VERSION 5.8 ;
BUSBITCHARS "[]" ;
DIVIDERCHAR "/" ;
UNITS
    DATABASE MICRONS 1000 ;
END UNITS

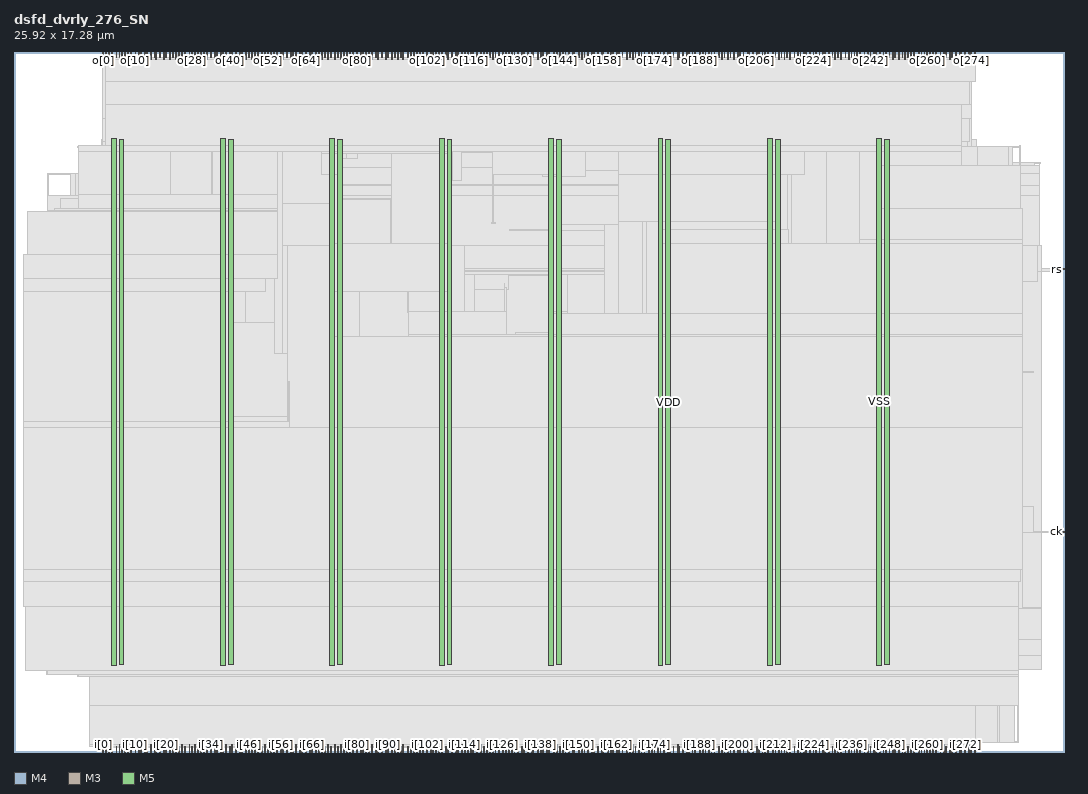
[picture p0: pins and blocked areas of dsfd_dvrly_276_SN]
MACRO dsfd_dvrly_276_SN
  FOREIGN dsfd_dvrly_276_SN 0 0 ;
  CLASS BLOCK ;
  SIZE 25.92 BY 17.28 ;
  PIN ck
    DIRECTION INPUT ;
    USE SIGNAL ;
    PORT
      LAYER M4 ;
        RECT  25.728 5.424 25.92 5.448 ;
    END
  END ck
  PIN i[0]
    DIRECTION INPUT ;
    USE SIGNAL ;
    PORT
      LAYER M3 ;
        RECT  2.196 0 2.214 0.144 ;
    END
  END i[0]
  PIN i[100]
    DIRECTION INPUT ;
    USE SIGNAL ;
    PORT
      LAYER M3 ;
        RECT  10.008 0 10.026 0.144 ;
    END
  END i[100]
  PIN i[101]
    DIRECTION INPUT ;
    USE SIGNAL ;
    PORT
      LAYER M5 ;
        RECT  10.08 0 10.104 0.192 ;
    END
  END i[101]
  PIN i[102]
    DIRECTION INPUT ;
    USE SIGNAL ;
    PORT
      LAYER M3 ;
        RECT  10.188 0 10.206 0.144 ;
    END
  END i[102]
  PIN i[103]
    DIRECTION INPUT ;
    USE SIGNAL ;
    PORT
      LAYER M5 ;
        RECT  10.272 0 10.296 0.192 ;
    END
  END i[103]
  PIN i[104]
    DIRECTION INPUT ;
    USE SIGNAL ;
    PORT
      LAYER M3 ;
        RECT  10.332 0 10.35 0.144 ;
    END
  END i[104]
  PIN i[105]
    DIRECTION INPUT ;
    USE SIGNAL ;
    PORT
      LAYER M5 ;
        RECT  10.416 0 10.44 0.192 ;
    END
  END i[105]
  PIN i[106]
    DIRECTION INPUT ;
    USE SIGNAL ;
    PORT
      LAYER M3 ;
        RECT  10.476 0 10.494 0.144 ;
    END
  END i[106]
  PIN i[107]
    DIRECTION INPUT ;
    USE SIGNAL ;
    PORT
      LAYER M5 ;
        RECT  10.56 0 10.584 0.192 ;
    END
  END i[107]
  PIN i[108]
    DIRECTION INPUT ;
    USE SIGNAL ;
    PORT
      LAYER M3 ;
        RECT  10.656 0 10.674 0.144 ;
    END
  END i[108]
  PIN i[109]
    DIRECTION INPUT ;
    USE SIGNAL ;
    PORT
      LAYER M5 ;
        RECT  10.704 0 10.728 0.192 ;
    END
  END i[109]
  PIN i[10]
    DIRECTION INPUT ;
    USE SIGNAL ;
    PORT
      LAYER M3 ;
        RECT  2.988 0 3.006 0.144 ;
    END
  END i[10]
  PIN i[110]
    DIRECTION INPUT ;
    USE SIGNAL ;
    PORT
      LAYER M3 ;
        RECT  10.8 0 10.818 0.144 ;
    END
  END i[110]
  PIN i[111]
    DIRECTION INPUT ;
    USE SIGNAL ;
    PORT
      LAYER M5 ;
        RECT  10.896 0 10.92 0.192 ;
    END
  END i[111]
  PIN i[112]
    DIRECTION INPUT ;
    USE SIGNAL ;
    PORT
      LAYER M3 ;
        RECT  10.944 0 10.962 0.144 ;
    END
  END i[112]
  PIN i[113]
    DIRECTION INPUT ;
    USE SIGNAL ;
    PORT
      LAYER M5 ;
        RECT  11.04 0 11.064 0.192 ;
    END
  END i[113]
  PIN i[114]
    DIRECTION INPUT ;
    USE SIGNAL ;
    PORT
      LAYER M3 ;
        RECT  11.124 0 11.142 0.144 ;
    END
  END i[114]
  PIN i[115]
    DIRECTION INPUT ;
    USE SIGNAL ;
    PORT
      LAYER M5 ;
        RECT  11.184 0 11.208 0.192 ;
    END
  END i[115]
  PIN i[116]
    DIRECTION INPUT ;
    USE SIGNAL ;
    PORT
      LAYER M3 ;
        RECT  11.268 0 11.286 0.144 ;
    END
  END i[116]
  PIN i[117]
    DIRECTION INPUT ;
    USE SIGNAL ;
    PORT
      LAYER M5 ;
        RECT  11.328 0 11.352 0.192 ;
    END
  END i[117]
  PIN i[118]
    DIRECTION INPUT ;
    USE SIGNAL ;
    PORT
      LAYER M3 ;
        RECT  11.412 0 11.43 0.144 ;
    END
  END i[118]
  PIN i[119]
    DIRECTION INPUT ;
    USE SIGNAL ;
    PORT
      LAYER M5 ;
        RECT  11.52 0 11.544 0.192 ;
    END
  END i[119]
  PIN i[11]
    DIRECTION INPUT ;
    USE SIGNAL ;
    PORT
      LAYER M5 ;
        RECT  3.072 0 3.096 0.192 ;
    END
  END i[11]
  PIN i[120]
    DIRECTION INPUT ;
    USE SIGNAL ;
    PORT
      LAYER M3 ;
        RECT  11.592 0 11.61 0.144 ;
    END
  END i[120]
  PIN i[121]
    DIRECTION INPUT ;
    USE SIGNAL ;
    PORT
      LAYER M5 ;
        RECT  11.664 0 11.688 0.192 ;
    END
  END i[121]
  PIN i[122]
    DIRECTION INPUT ;
    USE SIGNAL ;
    PORT
      LAYER M3 ;
        RECT  11.736 0 11.754 0.144 ;
    END
  END i[122]
  PIN i[123]
    DIRECTION INPUT ;
    USE SIGNAL ;
    PORT
      LAYER M5 ;
        RECT  11.808 0 11.832 0.192 ;
    END
  END i[123]
  PIN i[124]
    DIRECTION INPUT ;
    USE SIGNAL ;
    PORT
      LAYER M3 ;
        RECT  11.88 0 11.898 0.144 ;
    END
  END i[124]
  PIN i[125]
    DIRECTION INPUT ;
    USE SIGNAL ;
    PORT
      LAYER M5 ;
        RECT  11.952 0 11.976 0.192 ;
    END
  END i[125]
  PIN i[126]
    DIRECTION INPUT ;
    USE SIGNAL ;
    PORT
      LAYER M3 ;
        RECT  12.06 0 12.078 0.144 ;
    END
  END i[126]
  PIN i[127]
    DIRECTION INPUT ;
    USE SIGNAL ;
    PORT
      LAYER M5 ;
        RECT  12.144 0 12.168 0.192 ;
    END
  END i[127]
  PIN i[128]
    DIRECTION INPUT ;
    USE SIGNAL ;
    PORT
      LAYER M3 ;
        RECT  12.204 0 12.222 0.144 ;
    END
  END i[128]
  PIN i[129]
    DIRECTION INPUT ;
    USE SIGNAL ;
    PORT
      LAYER M5 ;
        RECT  12.288 0 12.312 0.192 ;
    END
  END i[129]
  PIN i[12]
    DIRECTION INPUT ;
    USE SIGNAL ;
    PORT
      LAYER M3 ;
        RECT  3.132 0 3.15 0.144 ;
    END
  END i[12]
  PIN i[130]
    DIRECTION INPUT ;
    USE SIGNAL ;
    PORT
      LAYER M3 ;
        RECT  12.348 0 12.366 0.144 ;
    END
  END i[130]
  PIN i[131]
    DIRECTION INPUT ;
    USE SIGNAL ;
    PORT
      LAYER M5 ;
        RECT  12.432 0 12.456 0.192 ;
    END
  END i[131]
  PIN i[132]
    DIRECTION INPUT ;
    USE SIGNAL ;
    PORT
      LAYER M3 ;
        RECT  12.528 0 12.546 0.144 ;
    END
  END i[132]
  PIN i[133]
    DIRECTION INPUT ;
    USE SIGNAL ;
    PORT
      LAYER M5 ;
        RECT  12.576 0 12.6 0.192 ;
    END
  END i[133]
  PIN i[134]
    DIRECTION INPUT ;
    USE SIGNAL ;
    PORT
      LAYER M3 ;
        RECT  12.672 0 12.69 0.144 ;
    END
  END i[134]
  PIN i[135]
    DIRECTION INPUT ;
    USE SIGNAL ;
    PORT
      LAYER M5 ;
        RECT  12.768 0 12.792 0.192 ;
    END
  END i[135]
  PIN i[136]
    DIRECTION INPUT ;
    USE SIGNAL ;
    PORT
      LAYER M3 ;
        RECT  12.816 0 12.834 0.144 ;
    END
  END i[136]
  PIN i[137]
    DIRECTION INPUT ;
    USE SIGNAL ;
    PORT
      LAYER M5 ;
        RECT  12.912 0 12.936 0.192 ;
    END
  END i[137]
  PIN i[138]
    DIRECTION INPUT ;
    USE SIGNAL ;
    PORT
      LAYER M3 ;
        RECT  12.996 0 13.014 0.144 ;
    END
  END i[138]
  PIN i[139]
    DIRECTION INPUT ;
    USE SIGNAL ;
    PORT
      LAYER M5 ;
        RECT  13.056 0 13.08 0.192 ;
    END
  END i[139]
  PIN i[13]
    DIRECTION INPUT ;
    USE SIGNAL ;
    PORT
      LAYER M5 ;
        RECT  3.216 0 3.24 0.192 ;
    END
  END i[13]
  PIN i[140]
    DIRECTION INPUT ;
    USE SIGNAL ;
    PORT
      LAYER M3 ;
        RECT  13.14 0 13.158 0.144 ;
    END
  END i[140]
  PIN i[141]
    DIRECTION INPUT ;
    USE SIGNAL ;
    PORT
      LAYER M5 ;
        RECT  13.2 0 13.224 0.192 ;
    END
  END i[141]
  PIN i[142]
    DIRECTION INPUT ;
    USE SIGNAL ;
    PORT
      LAYER M3 ;
        RECT  13.32 0 13.338 0.144 ;
    END
  END i[142]
  PIN i[143]
    DIRECTION INPUT ;
    USE SIGNAL ;
    PORT
      LAYER M5 ;
        RECT  13.392 0 13.416 0.192 ;
    END
  END i[143]
  PIN i[144]
    DIRECTION INPUT ;
    USE SIGNAL ;
    PORT
      LAYER M3 ;
        RECT  13.464 0 13.482 0.144 ;
    END
  END i[144]
  PIN i[145]
    DIRECTION INPUT ;
    USE SIGNAL ;
    PORT
      LAYER M5 ;
        RECT  13.536 0 13.56 0.192 ;
    END
  END i[145]
  PIN i[146]
    DIRECTION INPUT ;
    USE SIGNAL ;
    PORT
      LAYER M3 ;
        RECT  13.608 0 13.626 0.144 ;
    END
  END i[146]
  PIN i[147]
    DIRECTION INPUT ;
    USE SIGNAL ;
    PORT
      LAYER M5 ;
        RECT  13.68 0 13.704 0.192 ;
    END
  END i[147]
  PIN i[148]
    DIRECTION INPUT ;
    USE SIGNAL ;
    PORT
      LAYER M3 ;
        RECT  13.788 0 13.806 0.144 ;
    END
  END i[148]
  PIN i[149]
    DIRECTION INPUT ;
    USE SIGNAL ;
    PORT
      LAYER M5 ;
        RECT  13.824 0 13.848 0.192 ;
    END
  END i[149]
  PIN i[14]
    DIRECTION INPUT ;
    USE SIGNAL ;
    PORT
      LAYER M3 ;
        RECT  3.276 0 3.294 0.144 ;
    END
  END i[14]
  PIN i[150]
    DIRECTION INPUT ;
    USE SIGNAL ;
    PORT
      LAYER M3 ;
        RECT  13.932 0 13.95 0.144 ;
    END
  END i[150]
  PIN i[151]
    DIRECTION INPUT ;
    USE SIGNAL ;
    PORT
      LAYER M5 ;
        RECT  14.016 0 14.04 0.192 ;
    END
  END i[151]
  PIN i[152]
    DIRECTION INPUT ;
    USE SIGNAL ;
    PORT
      LAYER M3 ;
        RECT  14.076 0 14.094 0.144 ;
    END
  END i[152]
  PIN i[153]
    DIRECTION INPUT ;
    USE SIGNAL ;
    PORT
      LAYER M5 ;
        RECT  14.16 0 14.184 0.192 ;
    END
  END i[153]
  PIN i[154]
    DIRECTION INPUT ;
    USE SIGNAL ;
    PORT
      LAYER M3 ;
        RECT  14.256 0 14.274 0.144 ;
    END
  END i[154]
  PIN i[155]
    DIRECTION INPUT ;
    USE SIGNAL ;
    PORT
      LAYER M5 ;
        RECT  14.304 0 14.328 0.192 ;
    END
  END i[155]
  PIN i[156]
    DIRECTION INPUT ;
    USE SIGNAL ;
    PORT
      LAYER M3 ;
        RECT  14.4 0 14.418 0.144 ;
    END
  END i[156]
  PIN i[157]
    DIRECTION INPUT ;
    USE SIGNAL ;
    PORT
      LAYER M5 ;
        RECT  14.496 0 14.52 0.192 ;
    END
  END i[157]
  PIN i[158]
    DIRECTION INPUT ;
    USE SIGNAL ;
    PORT
      LAYER M3 ;
        RECT  14.544 0 14.562 0.144 ;
    END
  END i[158]
  PIN i[159]
    DIRECTION INPUT ;
    USE SIGNAL ;
    PORT
      LAYER M5 ;
        RECT  14.64 0 14.664 0.192 ;
    END
  END i[159]
  PIN i[15]
    DIRECTION INPUT ;
    USE SIGNAL ;
    PORT
      LAYER M5 ;
        RECT  3.36 0 3.384 0.192 ;
    END
  END i[15]
  PIN i[160]
    DIRECTION INPUT ;
    USE SIGNAL ;
    PORT
      LAYER M3 ;
        RECT  14.724 0 14.742 0.144 ;
    END
  END i[160]
  PIN i[161]
    DIRECTION INPUT ;
    USE SIGNAL ;
    PORT
      LAYER M5 ;
        RECT  14.784 0 14.808 0.192 ;
    END
  END i[161]
  PIN i[162]
    DIRECTION INPUT ;
    USE SIGNAL ;
    PORT
      LAYER M3 ;
        RECT  14.868 0 14.886 0.144 ;
    END
  END i[162]
  PIN i[163]
    DIRECTION INPUT ;
    USE SIGNAL ;
    PORT
      LAYER M5 ;
        RECT  14.928 0 14.952 0.192 ;
    END
  END i[163]
  PIN i[164]
    DIRECTION INPUT ;
    USE SIGNAL ;
    PORT
      LAYER M3 ;
        RECT  15.012 0 15.03 0.144 ;
    END
  END i[164]
  PIN i[165]
    DIRECTION INPUT ;
    USE SIGNAL ;
    PORT
      LAYER M5 ;
        RECT  15.12 0 15.144 0.192 ;
    END
  END i[165]
  PIN i[166]
    DIRECTION INPUT ;
    USE SIGNAL ;
    PORT
      LAYER M3 ;
        RECT  15.192 0 15.21 0.144 ;
    END
  END i[166]
  PIN i[167]
    DIRECTION INPUT ;
    USE SIGNAL ;
    PORT
      LAYER M5 ;
        RECT  15.264 0 15.288 0.192 ;
    END
  END i[167]
  PIN i[168]
    DIRECTION INPUT ;
    USE SIGNAL ;
    PORT
      LAYER M3 ;
        RECT  15.336 0 15.354 0.144 ;
    END
  END i[168]
  PIN i[169]
    DIRECTION INPUT ;
    USE SIGNAL ;
    PORT
      LAYER M5 ;
        RECT  15.408 0 15.432 0.192 ;
    END
  END i[169]
  PIN i[16]
    DIRECTION INPUT ;
    USE SIGNAL ;
    PORT
      LAYER M3 ;
        RECT  3.456 0 3.474 0.144 ;
    END
  END i[16]
  PIN i[170]
    DIRECTION INPUT ;
    USE SIGNAL ;
    PORT
      LAYER M3 ;
        RECT  15.48 0 15.498 0.144 ;
    END
  END i[170]
  PIN i[171]
    DIRECTION INPUT ;
    USE SIGNAL ;
    PORT
      LAYER M5 ;
        RECT  15.552 0 15.576 0.192 ;
    END
  END i[171]
  PIN i[172]
    DIRECTION INPUT ;
    USE SIGNAL ;
    PORT
      LAYER M3 ;
        RECT  15.66 0 15.678 0.144 ;
    END
  END i[172]
  PIN i[173]
    DIRECTION INPUT ;
    USE SIGNAL ;
    PORT
      LAYER M5 ;
        RECT  15.744 0 15.768 0.192 ;
    END
  END i[173]
  PIN i[174]
    DIRECTION INPUT ;
    USE SIGNAL ;
    PORT
      LAYER M3 ;
        RECT  15.804 0 15.822 0.144 ;
    END
  END i[174]
  PIN i[175]
    DIRECTION INPUT ;
    USE SIGNAL ;
    PORT
      LAYER M5 ;
        RECT  15.888 0 15.912 0.192 ;
    END
  END i[175]
  PIN i[176]
    DIRECTION INPUT ;
    USE SIGNAL ;
    PORT
      LAYER M3 ;
        RECT  15.948 0 15.966 0.144 ;
    END
  END i[176]
  PIN i[177]
    DIRECTION INPUT ;
    USE SIGNAL ;
    PORT
      LAYER M5 ;
        RECT  16.032 0 16.056 0.192 ;
    END
  END i[177]
  PIN i[178]
    DIRECTION INPUT ;
    USE SIGNAL ;
    PORT
      LAYER M3 ;
        RECT  16.128 0 16.146 0.144 ;
    END
  END i[178]
  PIN i[179]
    DIRECTION INPUT ;
    USE SIGNAL ;
    PORT
      LAYER M5 ;
        RECT  16.176 0 16.2 0.192 ;
    END
  END i[179]
  PIN i[17]
    DIRECTION INPUT ;
    USE SIGNAL ;
    PORT
      LAYER M5 ;
        RECT  3.504 0 3.528 0.192 ;
    END
  END i[17]
  PIN i[180]
    DIRECTION INPUT ;
    USE SIGNAL ;
    PORT
      LAYER M3 ;
        RECT  16.272 0 16.29 0.144 ;
    END
  END i[180]
  PIN i[181]
    DIRECTION INPUT ;
    USE SIGNAL ;
    PORT
      LAYER M5 ;
        RECT  16.368 0 16.392 0.192 ;
    END
  END i[181]
  PIN i[182]
    DIRECTION INPUT ;
    USE SIGNAL ;
    PORT
      LAYER M3 ;
        RECT  16.416 0 16.434 0.144 ;
    END
  END i[182]
  PIN i[183]
    DIRECTION INPUT ;
    USE SIGNAL ;
    PORT
      LAYER M5 ;
        RECT  16.512 0 16.536 0.192 ;
    END
  END i[183]
  PIN i[184]
    DIRECTION INPUT ;
    USE SIGNAL ;
    PORT
      LAYER M3 ;
        RECT  16.596 0 16.614 0.144 ;
    END
  END i[184]
  PIN i[185]
    DIRECTION INPUT ;
    USE SIGNAL ;
    PORT
      LAYER M5 ;
        RECT  16.656 0 16.68 0.192 ;
    END
  END i[185]
  PIN i[186]
    DIRECTION INPUT ;
    USE SIGNAL ;
    PORT
      LAYER M3 ;
        RECT  16.74 0 16.758 0.144 ;
    END
  END i[186]
  PIN i[187]
    DIRECTION INPUT ;
    USE SIGNAL ;
    PORT
      LAYER M5 ;
        RECT  16.8 0 16.824 0.192 ;
    END
  END i[187]
  PIN i[188]
    DIRECTION INPUT ;
    USE SIGNAL ;
    PORT
      LAYER M3 ;
        RECT  16.92 0 16.938 0.144 ;
    END
  END i[188]
  PIN i[189]
    DIRECTION INPUT ;
    USE SIGNAL ;
    PORT
      LAYER M5 ;
        RECT  16.992 0 17.016 0.192 ;
    END
  END i[189]
  PIN i[18]
    DIRECTION INPUT ;
    USE SIGNAL ;
    PORT
      LAYER M3 ;
        RECT  3.6 0 3.618 0.144 ;
    END
  END i[18]
  PIN i[190]
    DIRECTION INPUT ;
    USE SIGNAL ;
    PORT
      LAYER M3 ;
        RECT  17.064 0 17.082 0.144 ;
    END
  END i[190]
  PIN i[191]
    DIRECTION INPUT ;
    USE SIGNAL ;
    PORT
      LAYER M5 ;
        RECT  17.136 0 17.16 0.192 ;
    END
  END i[191]
  PIN i[192]
    DIRECTION INPUT ;
    USE SIGNAL ;
    PORT
      LAYER M3 ;
        RECT  17.208 0 17.226 0.144 ;
    END
  END i[192]
  PIN i[193]
    DIRECTION INPUT ;
    USE SIGNAL ;
    PORT
      LAYER M5 ;
        RECT  17.28 0 17.304 0.192 ;
    END
  END i[193]
  PIN i[194]
    DIRECTION INPUT ;
    USE SIGNAL ;
    PORT
      LAYER M3 ;
        RECT  17.388 0 17.406 0.144 ;
    END
  END i[194]
  PIN i[195]
    DIRECTION INPUT ;
    USE SIGNAL ;
    PORT
      LAYER M5 ;
        RECT  17.472 0 17.496 0.192 ;
    END
  END i[195]
  PIN i[196]
    DIRECTION INPUT ;
    USE SIGNAL ;
    PORT
      LAYER M3 ;
        RECT  17.532 0 17.55 0.144 ;
    END
  END i[196]
  PIN i[197]
    DIRECTION INPUT ;
    USE SIGNAL ;
    PORT
      LAYER M5 ;
        RECT  17.616 0 17.64 0.192 ;
    END
  END i[197]
  PIN i[198]
    DIRECTION INPUT ;
    USE SIGNAL ;
    PORT
      LAYER M3 ;
        RECT  17.676 0 17.694 0.144 ;
    END
  END i[198]
  PIN i[199]
    DIRECTION INPUT ;
    USE SIGNAL ;
    PORT
      LAYER M5 ;
        RECT  17.76 0 17.784 0.192 ;
    END
  END i[199]
  PIN i[19]
    DIRECTION INPUT ;
    USE SIGNAL ;
    PORT
      LAYER M5 ;
        RECT  3.696 0 3.72 0.192 ;
    END
  END i[19]
  PIN i[1]
    DIRECTION INPUT ;
    USE SIGNAL ;
    PORT
      LAYER M5 ;
        RECT  2.256 0 2.28 0.192 ;
    END
  END i[1]
  PIN i[200]
    DIRECTION INPUT ;
    USE SIGNAL ;
    PORT
      LAYER M3 ;
        RECT  17.856 0 17.874 0.144 ;
    END
  END i[200]
  PIN i[201]
    DIRECTION INPUT ;
    USE SIGNAL ;
    PORT
      LAYER M5 ;
        RECT  17.904 0 17.928 0.192 ;
    END
  END i[201]
  PIN i[202]
    DIRECTION INPUT ;
    USE SIGNAL ;
    PORT
      LAYER M3 ;
        RECT  18 0 18.018 0.144 ;
    END
  END i[202]
  PIN i[203]
    DIRECTION INPUT ;
    USE SIGNAL ;
    PORT
      LAYER M5 ;
        RECT  18.096 0 18.12 0.192 ;
    END
  END i[203]
  PIN i[204]
    DIRECTION INPUT ;
    USE SIGNAL ;
    PORT
      LAYER M3 ;
        RECT  18.144 0 18.162 0.144 ;
    END
  END i[204]
  PIN i[205]
    DIRECTION INPUT ;
    USE SIGNAL ;
    PORT
      LAYER M5 ;
        RECT  18.24 0 18.264 0.192 ;
    END
  END i[205]
  PIN i[206]
    DIRECTION INPUT ;
    USE SIGNAL ;
    PORT
      LAYER M3 ;
        RECT  18.324 0 18.342 0.144 ;
    END
  END i[206]
  PIN i[207]
    DIRECTION INPUT ;
    USE SIGNAL ;
    PORT
      LAYER M5 ;
        RECT  18.384 0 18.408 0.192 ;
    END
  END i[207]
  PIN i[208]
    DIRECTION INPUT ;
    USE SIGNAL ;
    PORT
      LAYER M3 ;
        RECT  18.468 0 18.486 0.144 ;
    END
  END i[208]
  PIN i[209]
    DIRECTION INPUT ;
    USE SIGNAL ;
    PORT
      LAYER M5 ;
        RECT  18.528 0 18.552 0.192 ;
    END
  END i[209]
  PIN i[20]
    DIRECTION INPUT ;
    USE SIGNAL ;
    PORT
      LAYER M3 ;
        RECT  3.744 0 3.762 0.144 ;
    END
  END i[20]
  PIN i[210]
    DIRECTION INPUT ;
    USE SIGNAL ;
    PORT
      LAYER M3 ;
        RECT  18.612 0 18.63 0.144 ;
    END
  END i[210]
  PIN i[211]
    DIRECTION INPUT ;
    USE SIGNAL ;
    PORT
      LAYER M5 ;
        RECT  18.72 0 18.744 0.192 ;
    END
  END i[211]
  PIN i[212]
    DIRECTION INPUT ;
    USE SIGNAL ;
    PORT
      LAYER M3 ;
        RECT  18.792 0 18.81 0.144 ;
    END
  END i[212]
  PIN i[213]
    DIRECTION INPUT ;
    USE SIGNAL ;
    PORT
      LAYER M5 ;
        RECT  18.864 0 18.888 0.192 ;
    END
  END i[213]
  PIN i[214]
    DIRECTION INPUT ;
    USE SIGNAL ;
    PORT
      LAYER M3 ;
        RECT  18.936 0 18.954 0.144 ;
    END
  END i[214]
  PIN i[215]
    DIRECTION INPUT ;
    USE SIGNAL ;
    PORT
      LAYER M5 ;
        RECT  19.008 0 19.032 0.192 ;
    END
  END i[215]
  PIN i[216]
    DIRECTION INPUT ;
    USE SIGNAL ;
    PORT
      LAYER M3 ;
        RECT  19.08 0 19.098 0.144 ;
    END
  END i[216]
  PIN i[217]
    DIRECTION INPUT ;
    USE SIGNAL ;
    PORT
      LAYER M5 ;
        RECT  19.152 0 19.176 0.192 ;
    END
  END i[217]
  PIN i[218]
    DIRECTION INPUT ;
    USE SIGNAL ;
    PORT
      LAYER M3 ;
        RECT  19.26 0 19.278 0.144 ;
    END
  END i[218]
  PIN i[219]
    DIRECTION INPUT ;
    USE SIGNAL ;
    PORT
      LAYER M5 ;
        RECT  19.344 0 19.368 0.192 ;
    END
  END i[219]
  PIN i[21]
    DIRECTION INPUT ;
    USE SIGNAL ;
    PORT
      LAYER M5 ;
        RECT  3.84 0 3.864 0.192 ;
    END
  END i[21]
  PIN i[220]
    DIRECTION INPUT ;
    USE SIGNAL ;
    PORT
      LAYER M3 ;
        RECT  19.404 0 19.422 0.144 ;
    END
  END i[220]
  PIN i[221]
    DIRECTION INPUT ;
    USE SIGNAL ;
    PORT
      LAYER M5 ;
        RECT  19.488 0 19.512 0.192 ;
    END
  END i[221]
  PIN i[222]
    DIRECTION INPUT ;
    USE SIGNAL ;
    PORT
      LAYER M3 ;
        RECT  19.548 0 19.566 0.144 ;
    END
  END i[222]
  PIN i[223]
    DIRECTION INPUT ;
    USE SIGNAL ;
    PORT
      LAYER M5 ;
        RECT  19.632 0 19.656 0.192 ;
    END
  END i[223]
  PIN i[224]
    DIRECTION INPUT ;
    USE SIGNAL ;
    PORT
      LAYER M3 ;
        RECT  19.728 0 19.746 0.144 ;
    END
  END i[224]
  PIN i[225]
    DIRECTION INPUT ;
    USE SIGNAL ;
    PORT
      LAYER M5 ;
        RECT  19.776 0 19.8 0.192 ;
    END
  END i[225]
  PIN i[226]
    DIRECTION INPUT ;
    USE SIGNAL ;
    PORT
      LAYER M3 ;
        RECT  19.872 0 19.89 0.144 ;
    END
  END i[226]
  PIN i[227]
    DIRECTION INPUT ;
    USE SIGNAL ;
    PORT
      LAYER M5 ;
        RECT  19.968 0 19.992 0.192 ;
    END
  END i[227]
  PIN i[228]
    DIRECTION INPUT ;
    USE SIGNAL ;
    PORT
      LAYER M3 ;
        RECT  20.016 0 20.034 0.144 ;
    END
  END i[228]
  PIN i[229]
    DIRECTION INPUT ;
    USE SIGNAL ;
    PORT
      LAYER M5 ;
        RECT  20.112 0 20.136 0.192 ;
    END
  END i[229]
  PIN i[22]
    DIRECTION INPUT ;
    USE SIGNAL ;
    PORT
      LAYER M3 ;
        RECT  3.924 0 3.942 0.144 ;
    END
  END i[22]
  PIN i[230]
    DIRECTION INPUT ;
    USE SIGNAL ;
    PORT
      LAYER M3 ;
        RECT  20.196 0 20.214 0.144 ;
    END
  END i[230]
  PIN i[231]
    DIRECTION INPUT ;
    USE SIGNAL ;
    PORT
      LAYER M5 ;
        RECT  20.256 0 20.28 0.192 ;
    END
  END i[231]
  PIN i[232]
    DIRECTION INPUT ;
    USE SIGNAL ;
    PORT
      LAYER M3 ;
        RECT  20.34 0 20.358 0.144 ;
    END
  END i[232]
  PIN i[233]
    DIRECTION INPUT ;
    USE SIGNAL ;
    PORT
      LAYER M5 ;
        RECT  20.4 0 20.424 0.192 ;
    END
  END i[233]
  PIN i[234]
    DIRECTION INPUT ;
    USE SIGNAL ;
    PORT
      LAYER M3 ;
        RECT  20.52 0 20.538 0.144 ;
    END
  END i[234]
  PIN i[235]
    DIRECTION INPUT ;
    USE SIGNAL ;
    PORT
      LAYER M5 ;
        RECT  20.592 0 20.616 0.192 ;
    END
  END i[235]
  PIN i[236]
    DIRECTION INPUT ;
    USE SIGNAL ;
    PORT
      LAYER M3 ;
        RECT  20.664 0 20.682 0.144 ;
    END
  END i[236]
  PIN i[237]
    DIRECTION INPUT ;
    USE SIGNAL ;
    PORT
      LAYER M5 ;
        RECT  20.736 0 20.76 0.192 ;
    END
  END i[237]
  PIN i[238]
    DIRECTION INPUT ;
    USE SIGNAL ;
    PORT
      LAYER M3 ;
        RECT  20.808 0 20.826 0.144 ;
    END
  END i[238]
  PIN i[239]
    DIRECTION INPUT ;
    USE SIGNAL ;
    PORT
      LAYER M5 ;
        RECT  20.88 0 20.904 0.192 ;
    END
  END i[239]
  PIN i[23]
    DIRECTION INPUT ;
    USE SIGNAL ;
    PORT
      LAYER M5 ;
        RECT  3.984 0 4.008 0.192 ;
    END
  END i[23]
  PIN i[240]
    DIRECTION INPUT ;
    USE SIGNAL ;
    PORT
      LAYER M3 ;
        RECT  20.988 0 21.006 0.144 ;
    END
  END i[240]
  PIN i[241]
    DIRECTION INPUT ;
    USE SIGNAL ;
    PORT
      LAYER M5 ;
        RECT  21.072 0 21.096 0.192 ;
    END
  END i[241]
  PIN i[242]
    DIRECTION INPUT ;
    USE SIGNAL ;
    PORT
      LAYER M3 ;
        RECT  21.132 0 21.15 0.144 ;
    END
  END i[242]
  PIN i[243]
    DIRECTION INPUT ;
    USE SIGNAL ;
    PORT
      LAYER M5 ;
        RECT  21.216 0 21.24 0.192 ;
    END
  END i[243]
  PIN i[244]
    DIRECTION INPUT ;
    USE SIGNAL ;
    PORT
      LAYER M3 ;
        RECT  21.276 0 21.294 0.144 ;
    END
  END i[244]
  PIN i[245]
    DIRECTION INPUT ;
    USE SIGNAL ;
    PORT
      LAYER M5 ;
        RECT  21.36 0 21.384 0.192 ;
    END
  END i[245]
  PIN i[246]
    DIRECTION INPUT ;
    USE SIGNAL ;
    PORT
      LAYER M3 ;
        RECT  21.456 0 21.474 0.144 ;
    END
  END i[246]
  PIN i[247]
    DIRECTION INPUT ;
    USE SIGNAL ;
    PORT
      LAYER M5 ;
        RECT  21.504 0 21.528 0.192 ;
    END
  END i[247]
  PIN i[248]
    DIRECTION INPUT ;
    USE SIGNAL ;
    PORT
      LAYER M3 ;
        RECT  21.6 0 21.618 0.144 ;
    END
  END i[248]
  PIN i[249]
    DIRECTION INPUT ;
    USE SIGNAL ;
    PORT
      LAYER M5 ;
        RECT  21.696 0 21.72 0.192 ;
    END
  END i[249]
  PIN i[24]
    DIRECTION INPUT ;
    USE SIGNAL ;
    PORT
      LAYER M3 ;
        RECT  4.068 0 4.086 0.144 ;
    END
  END i[24]
  PIN i[250]
    DIRECTION INPUT ;
    USE SIGNAL ;
    PORT
      LAYER M3 ;
        RECT  21.744 0 21.762 0.144 ;
    END
  END i[250]
  PIN i[251]
    DIRECTION INPUT ;
    USE SIGNAL ;
    PORT
      LAYER M5 ;
        RECT  21.84 0 21.864 0.192 ;
    END
  END i[251]
  PIN i[252]
    DIRECTION INPUT ;
    USE SIGNAL ;
    PORT
      LAYER M3 ;
        RECT  21.924 0 21.942 0.144 ;
    END
  END i[252]
  PIN i[253]
    DIRECTION INPUT ;
    USE SIGNAL ;
    PORT
      LAYER M5 ;
        RECT  21.984 0 22.008 0.192 ;
    END
  END i[253]
  PIN i[254]
    DIRECTION INPUT ;
    USE SIGNAL ;
    PORT
      LAYER M3 ;
        RECT  22.068 0 22.086 0.144 ;
    END
  END i[254]
  PIN i[255]
    DIRECTION INPUT ;
    USE SIGNAL ;
    PORT
      LAYER M5 ;
        RECT  22.128 0 22.152 0.192 ;
    END
  END i[255]
  PIN i[256]
    DIRECTION INPUT ;
    USE SIGNAL ;
    PORT
      LAYER M3 ;
        RECT  22.212 0 22.23 0.144 ;
    END
  END i[256]
  PIN i[257]
    DIRECTION INPUT ;
    USE SIGNAL ;
    PORT
      LAYER M5 ;
        RECT  22.32 0 22.344 0.192 ;
    END
  END i[257]
  PIN i[258]
    DIRECTION INPUT ;
    USE SIGNAL ;
    PORT
      LAYER M3 ;
        RECT  22.392 0 22.41 0.144 ;
    END
  END i[258]
  PIN i[259]
    DIRECTION INPUT ;
    USE SIGNAL ;
    PORT
      LAYER M5 ;
        RECT  22.464 0 22.488 0.192 ;
    END
  END i[259]
  PIN i[25]
    DIRECTION INPUT ;
    USE SIGNAL ;
    PORT
      LAYER M5 ;
        RECT  4.128 0 4.152 0.192 ;
    END
  END i[25]
  PIN i[260]
    DIRECTION INPUT ;
    USE SIGNAL ;
    PORT
      LAYER M3 ;
        RECT  22.536 0 22.554 0.144 ;
    END
  END i[260]
  PIN i[261]
    DIRECTION INPUT ;
    USE SIGNAL ;
    PORT
      LAYER M5 ;
        RECT  22.608 0 22.632 0.192 ;
    END
  END i[261]
  PIN i[262]
    DIRECTION INPUT ;
    USE SIGNAL ;
    PORT
      LAYER M3 ;
        RECT  22.68 0 22.698 0.144 ;
    END
  END i[262]
  PIN i[263]
    DIRECTION INPUT ;
    USE SIGNAL ;
    PORT
      LAYER M5 ;
        RECT  22.752 0 22.776 0.192 ;
    END
  END i[263]
  PIN i[264]
    DIRECTION INPUT ;
    USE SIGNAL ;
    PORT
      LAYER M3 ;
        RECT  22.86 0 22.878 0.144 ;
    END
  END i[264]
  PIN i[265]
    DIRECTION INPUT ;
    USE SIGNAL ;
    PORT
      LAYER M5 ;
        RECT  22.944 0 22.968 0.192 ;
    END
  END i[265]
  PIN i[266]
    DIRECTION INPUT ;
    USE SIGNAL ;
    PORT
      LAYER M3 ;
        RECT  23.004 0 23.022 0.144 ;
    END
  END i[266]
  PIN i[267]
    DIRECTION INPUT ;
    USE SIGNAL ;
    PORT
      LAYER M5 ;
        RECT  23.088 0 23.112 0.192 ;
    END
  END i[267]
  PIN i[268]
    DIRECTION INPUT ;
    USE SIGNAL ;
    PORT
      LAYER M3 ;
        RECT  23.148 0 23.166 0.144 ;
    END
  END i[268]
  PIN i[269]
    DIRECTION INPUT ;
    USE SIGNAL ;
    PORT
      LAYER M5 ;
        RECT  23.232 0 23.256 0.192 ;
    END
  END i[269]
  PIN i[26]
    DIRECTION INPUT ;
    USE SIGNAL ;
    PORT
      LAYER M3 ;
        RECT  4.212 0 4.23 0.144 ;
    END
  END i[26]
  PIN i[270]
    DIRECTION INPUT ;
    USE SIGNAL ;
    PORT
      LAYER M3 ;
        RECT  23.328 0 23.346 0.144 ;
    END
  END i[270]
  PIN i[271]
    DIRECTION INPUT ;
    USE SIGNAL ;
    PORT
      LAYER M5 ;
        RECT  23.376 0 23.4 0.192 ;
    END
  END i[271]
  PIN i[272]
    DIRECTION INPUT ;
    USE SIGNAL ;
    PORT
      LAYER M3 ;
        RECT  23.472 0 23.49 0.144 ;
    END
  END i[272]
  PIN i[273]
    DIRECTION INPUT ;
    USE SIGNAL ;
    PORT
      LAYER M5 ;
        RECT  23.568 0 23.592 0.192 ;
    END
  END i[273]
  PIN i[274]
    DIRECTION INPUT ;
    USE SIGNAL ;
    PORT
      LAYER M3 ;
        RECT  23.616 0 23.634 0.144 ;
    END
  END i[274]
  PIN i[275]
    DIRECTION INPUT ;
    USE SIGNAL ;
    PORT
      LAYER M5 ;
        RECT  23.712 0 23.736 0.192 ;
    END
  END i[275]
  PIN i[27]
    DIRECTION INPUT ;
    USE SIGNAL ;
    PORT
      LAYER M5 ;
        RECT  4.32 0 4.344 0.192 ;
    END
  END i[27]
  PIN i[28]
    DIRECTION INPUT ;
    USE SIGNAL ;
    PORT
      LAYER M3 ;
        RECT  4.392 0 4.41 0.144 ;
    END
  END i[28]
  PIN i[29]
    DIRECTION INPUT ;
    USE SIGNAL ;
    PORT
      LAYER M5 ;
        RECT  4.464 0 4.488 0.192 ;
    END
  END i[29]
  PIN i[2]
    DIRECTION INPUT ;
    USE SIGNAL ;
    PORT
      LAYER M3 ;
        RECT  2.34 0 2.358 0.144 ;
    END
  END i[2]
  PIN i[30]
    DIRECTION INPUT ;
    USE SIGNAL ;
    PORT
      LAYER M3 ;
        RECT  4.536 0 4.554 0.144 ;
    END
  END i[30]
  PIN i[31]
    DIRECTION INPUT ;
    USE SIGNAL ;
    PORT
      LAYER M5 ;
        RECT  4.608 0 4.632 0.192 ;
    END
  END i[31]
  PIN i[32]
    DIRECTION INPUT ;
    USE SIGNAL ;
    PORT
      LAYER M3 ;
        RECT  4.68 0 4.698 0.144 ;
    END
  END i[32]
  PIN i[33]
    DIRECTION INPUT ;
    USE SIGNAL ;
    PORT
      LAYER M5 ;
        RECT  4.752 0 4.776 0.192 ;
    END
  END i[33]
  PIN i[34]
    DIRECTION INPUT ;
    USE SIGNAL ;
    PORT
      LAYER M3 ;
        RECT  4.86 0 4.878 0.144 ;
    END
  END i[34]
  PIN i[35]
    DIRECTION INPUT ;
    USE SIGNAL ;
    PORT
      LAYER M5 ;
        RECT  4.944 0 4.968 0.192 ;
    END
  END i[35]
  PIN i[36]
    DIRECTION INPUT ;
    USE SIGNAL ;
    PORT
      LAYER M3 ;
        RECT  5.004 0 5.022 0.144 ;
    END
  END i[36]
  PIN i[37]
    DIRECTION INPUT ;
    USE SIGNAL ;
    PORT
      LAYER M5 ;
        RECT  5.088 0 5.112 0.192 ;
    END
  END i[37]
  PIN i[38]
    DIRECTION INPUT ;
    USE SIGNAL ;
    PORT
      LAYER M3 ;
        RECT  5.148 0 5.166 0.144 ;
    END
  END i[38]
  PIN i[39]
    DIRECTION INPUT ;
    USE SIGNAL ;
    PORT
      LAYER M5 ;
        RECT  5.232 0 5.256 0.192 ;
    END
  END i[39]
  PIN i[3]
    DIRECTION INPUT ;
    USE SIGNAL ;
    PORT
      LAYER M5 ;
        RECT  2.4 0 2.424 0.192 ;
    END
  END i[3]
  PIN i[40]
    DIRECTION INPUT ;
    USE SIGNAL ;
    PORT
      LAYER M3 ;
        RECT  5.328 0 5.346 0.144 ;
    END
  END i[40]
  PIN i[41]
    DIRECTION INPUT ;
    USE SIGNAL ;
    PORT
      LAYER M5 ;
        RECT  5.376 0 5.4 0.192 ;
    END
  END i[41]
  PIN i[42]
    DIRECTION INPUT ;
    USE SIGNAL ;
    PORT
      LAYER M3 ;
        RECT  5.472 0 5.49 0.144 ;
    END
  END i[42]
  PIN i[43]
    DIRECTION INPUT ;
    USE SIGNAL ;
    PORT
      LAYER M5 ;
        RECT  5.568 0 5.592 0.192 ;
    END
  END i[43]
  PIN i[44]
    DIRECTION INPUT ;
    USE SIGNAL ;
    PORT
      LAYER M3 ;
        RECT  5.616 0 5.634 0.144 ;
    END
  END i[44]
  PIN i[45]
    DIRECTION INPUT ;
    USE SIGNAL ;
    PORT
      LAYER M5 ;
        RECT  5.712 0 5.736 0.192 ;
    END
  END i[45]
  PIN i[46]
    DIRECTION INPUT ;
    USE SIGNAL ;
    PORT
      LAYER M3 ;
        RECT  5.796 0 5.814 0.144 ;
    END
  END i[46]
  PIN i[47]
    DIRECTION INPUT ;
    USE SIGNAL ;
    PORT
      LAYER M5 ;
        RECT  5.856 0 5.88 0.192 ;
    END
  END i[47]
  PIN i[48]
    DIRECTION INPUT ;
    USE SIGNAL ;
    PORT
      LAYER M3 ;
        RECT  5.94 0 5.958 0.144 ;
    END
  END i[48]
  PIN i[49]
    DIRECTION INPUT ;
    USE SIGNAL ;
    PORT
      LAYER M5 ;
        RECT  6 0 6.024 0.192 ;
    END
  END i[49]
  PIN i[4]
    DIRECTION INPUT ;
    USE SIGNAL ;
    PORT
      LAYER M3 ;
        RECT  2.52 0 2.538 0.144 ;
    END
  END i[4]
  PIN i[50]
    DIRECTION INPUT ;
    USE SIGNAL ;
    PORT
      LAYER M3 ;
        RECT  6.12 0 6.138 0.144 ;
    END
  END i[50]
  PIN i[51]
    DIRECTION INPUT ;
    USE SIGNAL ;
    PORT
      LAYER M5 ;
        RECT  6.192 0 6.216 0.192 ;
    END
  END i[51]
  PIN i[52]
    DIRECTION INPUT ;
    USE SIGNAL ;
    PORT
      LAYER M3 ;
        RECT  6.264 0 6.282 0.144 ;
    END
  END i[52]
  PIN i[53]
    DIRECTION INPUT ;
    USE SIGNAL ;
    PORT
      LAYER M5 ;
        RECT  6.336 0 6.36 0.192 ;
    END
  END i[53]
  PIN i[54]
    DIRECTION INPUT ;
    USE SIGNAL ;
    PORT
      LAYER M3 ;
        RECT  6.408 0 6.426 0.144 ;
    END
  END i[54]
  PIN i[55]
    DIRECTION INPUT ;
    USE SIGNAL ;
    PORT
      LAYER M5 ;
        RECT  6.48 0 6.504 0.192 ;
    END
  END i[55]
  PIN i[56]
    DIRECTION INPUT ;
    USE SIGNAL ;
    PORT
      LAYER M3 ;
        RECT  6.588 0 6.606 0.144 ;
    END
  END i[56]
  PIN i[57]
    DIRECTION INPUT ;
    USE SIGNAL ;
    PORT
      LAYER M5 ;
        RECT  6.624 0 6.648 0.192 ;
    END
  END i[57]
  PIN i[58]
    DIRECTION INPUT ;
    USE SIGNAL ;
    PORT
      LAYER M3 ;
        RECT  6.732 0 6.75 0.144 ;
    END
  END i[58]
  PIN i[59]
    DIRECTION INPUT ;
    USE SIGNAL ;
    PORT
      LAYER M5 ;
        RECT  6.816 0 6.84 0.192 ;
    END
  END i[59]
  PIN i[5]
    DIRECTION INPUT ;
    USE SIGNAL ;
    PORT
      LAYER M5 ;
        RECT  2.592 0 2.616 0.192 ;
    END
  END i[5]
  PIN i[60]
    DIRECTION INPUT ;
    USE SIGNAL ;
    PORT
      LAYER M3 ;
        RECT  6.876 0 6.894 0.144 ;
    END
  END i[60]
  PIN i[61]
    DIRECTION INPUT ;
    USE SIGNAL ;
    PORT
      LAYER M5 ;
        RECT  6.96 0 6.984 0.192 ;
    END
  END i[61]
  PIN i[62]
    DIRECTION INPUT ;
    USE SIGNAL ;
    PORT
      LAYER M3 ;
        RECT  7.056 0 7.074 0.144 ;
    END
  END i[62]
  PIN i[63]
    DIRECTION INPUT ;
    USE SIGNAL ;
    PORT
      LAYER M5 ;
        RECT  7.104 0 7.128 0.192 ;
    END
  END i[63]
  PIN i[64]
    DIRECTION INPUT ;
    USE SIGNAL ;
    PORT
      LAYER M3 ;
        RECT  7.2 0 7.218 0.144 ;
    END
  END i[64]
  PIN i[65]
    DIRECTION INPUT ;
    USE SIGNAL ;
    PORT
      LAYER M5 ;
        RECT  7.296 0 7.32 0.192 ;
    END
  END i[65]
  PIN i[66]
    DIRECTION INPUT ;
    USE SIGNAL ;
    PORT
      LAYER M3 ;
        RECT  7.344 0 7.362 0.144 ;
    END
  END i[66]
  PIN i[67]
    DIRECTION INPUT ;
    USE SIGNAL ;
    PORT
      LAYER M5 ;
        RECT  7.44 0 7.464 0.192 ;
    END
  END i[67]
  PIN i[68]
    DIRECTION INPUT ;
    USE SIGNAL ;
    PORT
      LAYER M3 ;
        RECT  7.524 0 7.542 0.144 ;
    END
  END i[68]
  PIN i[69]
    DIRECTION INPUT ;
    USE SIGNAL ;
    PORT
      LAYER M5 ;
        RECT  7.584 0 7.608 0.192 ;
    END
  END i[69]
  PIN i[6]
    DIRECTION INPUT ;
    USE SIGNAL ;
    PORT
      LAYER M3 ;
        RECT  2.664 0 2.682 0.144 ;
    END
  END i[6]
  PIN i[70]
    DIRECTION INPUT ;
    USE SIGNAL ;
    PORT
      LAYER M3 ;
        RECT  7.668 0 7.686 0.144 ;
    END
  END i[70]
  PIN i[71]
    DIRECTION INPUT ;
    USE SIGNAL ;
    PORT
      LAYER M5 ;
        RECT  7.728 0 7.752 0.192 ;
    END
  END i[71]
  PIN i[72]
    DIRECTION INPUT ;
    USE SIGNAL ;
    PORT
      LAYER M3 ;
        RECT  7.812 0 7.83 0.144 ;
    END
  END i[72]
  PIN i[73]
    DIRECTION INPUT ;
    USE SIGNAL ;
    PORT
      LAYER M5 ;
        RECT  7.92 0 7.944 0.192 ;
    END
  END i[73]
  PIN i[74]
    DIRECTION INPUT ;
    USE SIGNAL ;
    PORT
      LAYER M3 ;
        RECT  7.992 0 8.01 0.144 ;
    END
  END i[74]
  PIN i[75]
    DIRECTION INPUT ;
    USE SIGNAL ;
    PORT
      LAYER M5 ;
        RECT  8.064 0 8.088 0.192 ;
    END
  END i[75]
  PIN i[76]
    DIRECTION INPUT ;
    USE SIGNAL ;
    PORT
      LAYER M3 ;
        RECT  8.136 0 8.154 0.144 ;
    END
  END i[76]
  PIN i[77]
    DIRECTION INPUT ;
    USE SIGNAL ;
    PORT
      LAYER M5 ;
        RECT  8.208 0 8.232 0.192 ;
    END
  END i[77]
  PIN i[78]
    DIRECTION INPUT ;
    USE SIGNAL ;
    PORT
      LAYER M3 ;
        RECT  8.28 0 8.298 0.144 ;
    END
  END i[78]
  PIN i[79]
    DIRECTION INPUT ;
    USE SIGNAL ;
    PORT
      LAYER M5 ;
        RECT  8.352 0 8.376 0.192 ;
    END
  END i[79]
  PIN i[7]
    DIRECTION INPUT ;
    USE SIGNAL ;
    PORT
      LAYER M5 ;
        RECT  2.736 0 2.76 0.192 ;
    END
  END i[7]
  PIN i[80]
    DIRECTION INPUT ;
    USE SIGNAL ;
    PORT
      LAYER M3 ;
        RECT  8.46 0 8.478 0.144 ;
    END
  END i[80]
  PIN i[81]
    DIRECTION INPUT ;
    USE SIGNAL ;
    PORT
      LAYER M5 ;
        RECT  8.544 0 8.568 0.192 ;
    END
  END i[81]
  PIN i[82]
    DIRECTION INPUT ;
    USE SIGNAL ;
    PORT
      LAYER M3 ;
        RECT  8.604 0 8.622 0.144 ;
    END
  END i[82]
  PIN i[83]
    DIRECTION INPUT ;
    USE SIGNAL ;
    PORT
      LAYER M5 ;
        RECT  8.688 0 8.712 0.192 ;
    END
  END i[83]
  PIN i[84]
    DIRECTION INPUT ;
    USE SIGNAL ;
    PORT
      LAYER M3 ;
        RECT  8.748 0 8.766 0.144 ;
    END
  END i[84]
  PIN i[85]
    DIRECTION INPUT ;
    USE SIGNAL ;
    PORT
      LAYER M5 ;
        RECT  8.832 0 8.856 0.192 ;
    END
  END i[85]
  PIN i[86]
    DIRECTION INPUT ;
    USE SIGNAL ;
    PORT
      LAYER M3 ;
        RECT  8.928 0 8.946 0.144 ;
    END
  END i[86]
  PIN i[87]
    DIRECTION INPUT ;
    USE SIGNAL ;
    PORT
      LAYER M5 ;
        RECT  8.976 0 9 0.192 ;
    END
  END i[87]
  PIN i[88]
    DIRECTION INPUT ;
    USE SIGNAL ;
    PORT
      LAYER M3 ;
        RECT  9.072 0 9.09 0.144 ;
    END
  END i[88]
  PIN i[89]
    DIRECTION INPUT ;
    USE SIGNAL ;
    PORT
      LAYER M5 ;
        RECT  9.168 0 9.192 0.192 ;
    END
  END i[89]
  PIN i[8]
    DIRECTION INPUT ;
    USE SIGNAL ;
    PORT
      LAYER M3 ;
        RECT  2.808 0 2.826 0.144 ;
    END
  END i[8]
  PIN i[90]
    DIRECTION INPUT ;
    USE SIGNAL ;
    PORT
      LAYER M3 ;
        RECT  9.216 0 9.234 0.144 ;
    END
  END i[90]
  PIN i[91]
    DIRECTION INPUT ;
    USE SIGNAL ;
    PORT
      LAYER M5 ;
        RECT  9.312 0 9.336 0.192 ;
    END
  END i[91]
  PIN i[92]
    DIRECTION INPUT ;
    USE SIGNAL ;
    PORT
      LAYER M3 ;
        RECT  9.396 0 9.414 0.144 ;
    END
  END i[92]
  PIN i[93]
    DIRECTION INPUT ;
    USE SIGNAL ;
    PORT
      LAYER M5 ;
        RECT  9.456 0 9.48 0.192 ;
    END
  END i[93]
  PIN i[94]
    DIRECTION INPUT ;
    USE SIGNAL ;
    PORT
      LAYER M3 ;
        RECT  9.54 0 9.558 0.144 ;
    END
  END i[94]
  PIN i[95]
    DIRECTION INPUT ;
    USE SIGNAL ;
    PORT
      LAYER M5 ;
        RECT  9.6 0 9.624 0.192 ;
    END
  END i[95]
  PIN i[96]
    DIRECTION INPUT ;
    USE SIGNAL ;
    PORT
      LAYER M3 ;
        RECT  9.72 0 9.738 0.144 ;
    END
  END i[96]
  PIN i[97]
    DIRECTION INPUT ;
    USE SIGNAL ;
    PORT
      LAYER M5 ;
        RECT  9.792 0 9.816 0.192 ;
    END
  END i[97]
  PIN i[98]
    DIRECTION INPUT ;
    USE SIGNAL ;
    PORT
      LAYER M3 ;
        RECT  9.864 0 9.882 0.144 ;
    END
  END i[98]
  PIN i[99]
    DIRECTION INPUT ;
    USE SIGNAL ;
    PORT
      LAYER M5 ;
        RECT  9.936 0 9.96 0.192 ;
    END
  END i[99]
  PIN i[9]
    DIRECTION INPUT ;
    USE SIGNAL ;
    PORT
      LAYER M5 ;
        RECT  2.88 0 2.904 0.192 ;
    END
  END i[9]
  PIN o[0]
    DIRECTION OUTPUT ;
    USE SIGNAL ;
    PORT
      LAYER M3 ;
        RECT  2.196 17.136 2.214 17.28 ;
    END
  END o[0]
  PIN o[100]
    DIRECTION OUTPUT ;
    USE SIGNAL ;
    PORT
      LAYER M3 ;
        RECT  10.008 17.136 10.026 17.28 ;
    END
  END o[100]
  PIN o[101]
    DIRECTION OUTPUT ;
    USE SIGNAL ;
    PORT
      LAYER M5 ;
        RECT  10.08 17.088 10.104 17.28 ;
    END
  END o[101]
  PIN o[102]
    DIRECTION OUTPUT ;
    USE SIGNAL ;
    PORT
      LAYER M3 ;
        RECT  10.188 17.136 10.206 17.28 ;
    END
  END o[102]
  PIN o[103]
    DIRECTION OUTPUT ;
    USE SIGNAL ;
    PORT
      LAYER M5 ;
        RECT  10.272 17.088 10.296 17.28 ;
    END
  END o[103]
  PIN o[104]
    DIRECTION OUTPUT ;
    USE SIGNAL ;
    PORT
      LAYER M3 ;
        RECT  10.332 17.136 10.35 17.28 ;
    END
  END o[104]
  PIN o[105]
    DIRECTION OUTPUT ;
    USE SIGNAL ;
    PORT
      LAYER M5 ;
        RECT  10.416 17.088 10.44 17.28 ;
    END
  END o[105]
  PIN o[106]
    DIRECTION OUTPUT ;
    USE SIGNAL ;
    PORT
      LAYER M3 ;
        RECT  10.476 17.136 10.494 17.28 ;
    END
  END o[106]
  PIN o[107]
    DIRECTION OUTPUT ;
    USE SIGNAL ;
    PORT
      LAYER M5 ;
        RECT  10.56 17.088 10.584 17.28 ;
    END
  END o[107]
  PIN o[108]
    DIRECTION OUTPUT ;
    USE SIGNAL ;
    PORT
      LAYER M3 ;
        RECT  10.656 17.136 10.674 17.28 ;
    END
  END o[108]
  PIN o[109]
    DIRECTION OUTPUT ;
    USE SIGNAL ;
    PORT
      LAYER M5 ;
        RECT  10.704 17.088 10.728 17.28 ;
    END
  END o[109]
  PIN o[10]
    DIRECTION OUTPUT ;
    USE SIGNAL ;
    PORT
      LAYER M3 ;
        RECT  2.988 17.136 3.006 17.28 ;
    END
  END o[10]
  PIN o[110]
    DIRECTION OUTPUT ;
    USE SIGNAL ;
    PORT
      LAYER M3 ;
        RECT  10.8 17.136 10.818 17.28 ;
    END
  END o[110]
  PIN o[111]
    DIRECTION OUTPUT ;
    USE SIGNAL ;
    PORT
      LAYER M5 ;
        RECT  10.896 17.088 10.92 17.28 ;
    END
  END o[111]
  PIN o[112]
    DIRECTION OUTPUT ;
    USE SIGNAL ;
    PORT
      LAYER M3 ;
        RECT  10.944 17.136 10.962 17.28 ;
    END
  END o[112]
  PIN o[113]
    DIRECTION OUTPUT ;
    USE SIGNAL ;
    PORT
      LAYER M5 ;
        RECT  11.04 17.088 11.064 17.28 ;
    END
  END o[113]
  PIN o[114]
    DIRECTION OUTPUT ;
    USE SIGNAL ;
    PORT
      LAYER M3 ;
        RECT  11.124 17.136 11.142 17.28 ;
    END
  END o[114]
  PIN o[115]
    DIRECTION OUTPUT ;
    USE SIGNAL ;
    PORT
      LAYER M5 ;
        RECT  11.184 17.088 11.208 17.28 ;
    END
  END o[115]
  PIN o[116]
    DIRECTION OUTPUT ;
    USE SIGNAL ;
    PORT
      LAYER M3 ;
        RECT  11.268 17.136 11.286 17.28 ;
    END
  END o[116]
  PIN o[117]
    DIRECTION OUTPUT ;
    USE SIGNAL ;
    PORT
      LAYER M5 ;
        RECT  11.328 17.088 11.352 17.28 ;
    END
  END o[117]
  PIN o[118]
    DIRECTION OUTPUT ;
    USE SIGNAL ;
    PORT
      LAYER M3 ;
        RECT  11.412 17.136 11.43 17.28 ;
    END
  END o[118]
  PIN o[119]
    DIRECTION OUTPUT ;
    USE SIGNAL ;
    PORT
      LAYER M5 ;
        RECT  11.52 17.088 11.544 17.28 ;
    END
  END o[119]
  PIN o[11]
    DIRECTION OUTPUT ;
    USE SIGNAL ;
    PORT
      LAYER M5 ;
        RECT  3.072 17.088 3.096 17.28 ;
    END
  END o[11]
  PIN o[120]
    DIRECTION OUTPUT ;
    USE SIGNAL ;
    PORT
      LAYER M3 ;
        RECT  11.592 17.136 11.61 17.28 ;
    END
  END o[120]
  PIN o[121]
    DIRECTION OUTPUT ;
    USE SIGNAL ;
    PORT
      LAYER M5 ;
        RECT  11.664 17.088 11.688 17.28 ;
    END
  END o[121]
  PIN o[122]
    DIRECTION OUTPUT ;
    USE SIGNAL ;
    PORT
      LAYER M3 ;
        RECT  11.736 17.136 11.754 17.28 ;
    END
  END o[122]
  PIN o[123]
    DIRECTION OUTPUT ;
    USE SIGNAL ;
    PORT
      LAYER M5 ;
        RECT  11.808 17.088 11.832 17.28 ;
    END
  END o[123]
  PIN o[124]
    DIRECTION OUTPUT ;
    USE SIGNAL ;
    PORT
      LAYER M3 ;
        RECT  11.88 17.136 11.898 17.28 ;
    END
  END o[124]
  PIN o[125]
    DIRECTION OUTPUT ;
    USE SIGNAL ;
    PORT
      LAYER M5 ;
        RECT  11.952 17.088 11.976 17.28 ;
    END
  END o[125]
  PIN o[126]
    DIRECTION OUTPUT ;
    USE SIGNAL ;
    PORT
      LAYER M3 ;
        RECT  12.06 17.136 12.078 17.28 ;
    END
  END o[126]
  PIN o[127]
    DIRECTION OUTPUT ;
    USE SIGNAL ;
    PORT
      LAYER M5 ;
        RECT  12.144 17.088 12.168 17.28 ;
    END
  END o[127]
  PIN o[128]
    DIRECTION OUTPUT ;
    USE SIGNAL ;
    PORT
      LAYER M3 ;
        RECT  12.204 17.136 12.222 17.28 ;
    END
  END o[128]
  PIN o[129]
    DIRECTION OUTPUT ;
    USE SIGNAL ;
    PORT
      LAYER M5 ;
        RECT  12.288 17.088 12.312 17.28 ;
    END
  END o[129]
  PIN o[12]
    DIRECTION OUTPUT ;
    USE SIGNAL ;
    PORT
      LAYER M3 ;
        RECT  3.132 17.136 3.15 17.28 ;
    END
  END o[12]
  PIN o[130]
    DIRECTION OUTPUT ;
    USE SIGNAL ;
    PORT
      LAYER M3 ;
        RECT  12.348 17.136 12.366 17.28 ;
    END
  END o[130]
  PIN o[131]
    DIRECTION OUTPUT ;
    USE SIGNAL ;
    PORT
      LAYER M5 ;
        RECT  12.432 17.088 12.456 17.28 ;
    END
  END o[131]
  PIN o[132]
    DIRECTION OUTPUT ;
    USE SIGNAL ;
    PORT
      LAYER M3 ;
        RECT  12.528 17.136 12.546 17.28 ;
    END
  END o[132]
  PIN o[133]
    DIRECTION OUTPUT ;
    USE SIGNAL ;
    PORT
      LAYER M5 ;
        RECT  12.576 17.088 12.6 17.28 ;
    END
  END o[133]
  PIN o[134]
    DIRECTION OUTPUT ;
    USE SIGNAL ;
    PORT
      LAYER M3 ;
        RECT  12.672 17.136 12.69 17.28 ;
    END
  END o[134]
  PIN o[135]
    DIRECTION OUTPUT ;
    USE SIGNAL ;
    PORT
      LAYER M5 ;
        RECT  12.768 17.088 12.792 17.28 ;
    END
  END o[135]
  PIN o[136]
    DIRECTION OUTPUT ;
    USE SIGNAL ;
    PORT
      LAYER M3 ;
        RECT  12.816 17.136 12.834 17.28 ;
    END
  END o[136]
  PIN o[137]
    DIRECTION OUTPUT ;
    USE SIGNAL ;
    PORT
      LAYER M5 ;
        RECT  12.912 17.088 12.936 17.28 ;
    END
  END o[137]
  PIN o[138]
    DIRECTION OUTPUT ;
    USE SIGNAL ;
    PORT
      LAYER M3 ;
        RECT  12.996 17.136 13.014 17.28 ;
    END
  END o[138]
  PIN o[139]
    DIRECTION OUTPUT ;
    USE SIGNAL ;
    PORT
      LAYER M5 ;
        RECT  13.056 17.088 13.08 17.28 ;
    END
  END o[139]
  PIN o[13]
    DIRECTION OUTPUT ;
    USE SIGNAL ;
    PORT
      LAYER M5 ;
        RECT  3.216 17.088 3.24 17.28 ;
    END
  END o[13]
  PIN o[140]
    DIRECTION OUTPUT ;
    USE SIGNAL ;
    PORT
      LAYER M3 ;
        RECT  13.14 17.136 13.158 17.28 ;
    END
  END o[140]
  PIN o[141]
    DIRECTION OUTPUT ;
    USE SIGNAL ;
    PORT
      LAYER M5 ;
        RECT  13.2 17.088 13.224 17.28 ;
    END
  END o[141]
  PIN o[142]
    DIRECTION OUTPUT ;
    USE SIGNAL ;
    PORT
      LAYER M3 ;
        RECT  13.32 17.136 13.338 17.28 ;
    END
  END o[142]
  PIN o[143]
    DIRECTION OUTPUT ;
    USE SIGNAL ;
    PORT
      LAYER M5 ;
        RECT  13.392 17.088 13.416 17.28 ;
    END
  END o[143]
  PIN o[144]
    DIRECTION OUTPUT ;
    USE SIGNAL ;
    PORT
      LAYER M3 ;
        RECT  13.464 17.136 13.482 17.28 ;
    END
  END o[144]
  PIN o[145]
    DIRECTION OUTPUT ;
    USE SIGNAL ;
    PORT
      LAYER M5 ;
        RECT  13.536 17.088 13.56 17.28 ;
    END
  END o[145]
  PIN o[146]
    DIRECTION OUTPUT ;
    USE SIGNAL ;
    PORT
      LAYER M3 ;
        RECT  13.608 17.136 13.626 17.28 ;
    END
  END o[146]
  PIN o[147]
    DIRECTION OUTPUT ;
    USE SIGNAL ;
    PORT
      LAYER M5 ;
        RECT  13.68 17.088 13.704 17.28 ;
    END
  END o[147]
  PIN o[148]
    DIRECTION OUTPUT ;
    USE SIGNAL ;
    PORT
      LAYER M3 ;
        RECT  13.788 17.136 13.806 17.28 ;
    END
  END o[148]
  PIN o[149]
    DIRECTION OUTPUT ;
    USE SIGNAL ;
    PORT
      LAYER M5 ;
        RECT  13.824 17.088 13.848 17.28 ;
    END
  END o[149]
  PIN o[14]
    DIRECTION OUTPUT ;
    USE SIGNAL ;
    PORT
      LAYER M3 ;
        RECT  3.276 17.136 3.294 17.28 ;
    END
  END o[14]
  PIN o[150]
    DIRECTION OUTPUT ;
    USE SIGNAL ;
    PORT
      LAYER M3 ;
        RECT  13.932 17.136 13.95 17.28 ;
    END
  END o[150]
  PIN o[151]
    DIRECTION OUTPUT ;
    USE SIGNAL ;
    PORT
      LAYER M5 ;
        RECT  14.016 17.088 14.04 17.28 ;
    END
  END o[151]
  PIN o[152]
    DIRECTION OUTPUT ;
    USE SIGNAL ;
    PORT
      LAYER M3 ;
        RECT  14.076 17.136 14.094 17.28 ;
    END
  END o[152]
  PIN o[153]
    DIRECTION OUTPUT ;
    USE SIGNAL ;
    PORT
      LAYER M5 ;
        RECT  14.16 17.088 14.184 17.28 ;
    END
  END o[153]
  PIN o[154]
    DIRECTION OUTPUT ;
    USE SIGNAL ;
    PORT
      LAYER M3 ;
        RECT  14.256 17.136 14.274 17.28 ;
    END
  END o[154]
  PIN o[155]
    DIRECTION OUTPUT ;
    USE SIGNAL ;
    PORT
      LAYER M5 ;
        RECT  14.304 17.088 14.328 17.28 ;
    END
  END o[155]
  PIN o[156]
    DIRECTION OUTPUT ;
    USE SIGNAL ;
    PORT
      LAYER M3 ;
        RECT  14.4 17.136 14.418 17.28 ;
    END
  END o[156]
  PIN o[157]
    DIRECTION OUTPUT ;
    USE SIGNAL ;
    PORT
      LAYER M5 ;
        RECT  14.496 17.088 14.52 17.28 ;
    END
  END o[157]
  PIN o[158]
    DIRECTION OUTPUT ;
    USE SIGNAL ;
    PORT
      LAYER M3 ;
        RECT  14.544 17.136 14.562 17.28 ;
    END
  END o[158]
  PIN o[159]
    DIRECTION OUTPUT ;
    USE SIGNAL ;
    PORT
      LAYER M5 ;
        RECT  14.64 17.088 14.664 17.28 ;
    END
  END o[159]
  PIN o[15]
    DIRECTION OUTPUT ;
    USE SIGNAL ;
    PORT
      LAYER M5 ;
        RECT  3.36 17.088 3.384 17.28 ;
    END
  END o[15]
  PIN o[160]
    DIRECTION OUTPUT ;
    USE SIGNAL ;
    PORT
      LAYER M3 ;
        RECT  14.724 17.136 14.742 17.28 ;
    END
  END o[160]
  PIN o[161]
    DIRECTION OUTPUT ;
    USE SIGNAL ;
    PORT
      LAYER M5 ;
        RECT  14.784 17.088 14.808 17.28 ;
    END
  END o[161]
  PIN o[162]
    DIRECTION OUTPUT ;
    USE SIGNAL ;
    PORT
      LAYER M3 ;
        RECT  14.868 17.136 14.886 17.28 ;
    END
  END o[162]
  PIN o[163]
    DIRECTION OUTPUT ;
    USE SIGNAL ;
    PORT
      LAYER M5 ;
        RECT  14.928 17.088 14.952 17.28 ;
    END
  END o[163]
  PIN o[164]
    DIRECTION OUTPUT ;
    USE SIGNAL ;
    PORT
      LAYER M3 ;
        RECT  15.012 17.136 15.03 17.28 ;
    END
  END o[164]
  PIN o[165]
    DIRECTION OUTPUT ;
    USE SIGNAL ;
    PORT
      LAYER M5 ;
        RECT  15.12 17.088 15.144 17.28 ;
    END
  END o[165]
  PIN o[166]
    DIRECTION OUTPUT ;
    USE SIGNAL ;
    PORT
      LAYER M3 ;
        RECT  15.192 17.136 15.21 17.28 ;
    END
  END o[166]
  PIN o[167]
    DIRECTION OUTPUT ;
    USE SIGNAL ;
    PORT
      LAYER M5 ;
        RECT  15.264 17.088 15.288 17.28 ;
    END
  END o[167]
  PIN o[168]
    DIRECTION OUTPUT ;
    USE SIGNAL ;
    PORT
      LAYER M3 ;
        RECT  15.336 17.136 15.354 17.28 ;
    END
  END o[168]
  PIN o[169]
    DIRECTION OUTPUT ;
    USE SIGNAL ;
    PORT
      LAYER M5 ;
        RECT  15.408 17.088 15.432 17.28 ;
    END
  END o[169]
  PIN o[16]
    DIRECTION OUTPUT ;
    USE SIGNAL ;
    PORT
      LAYER M3 ;
        RECT  3.456 17.136 3.474 17.28 ;
    END
  END o[16]
  PIN o[170]
    DIRECTION OUTPUT ;
    USE SIGNAL ;
    PORT
      LAYER M3 ;
        RECT  15.48 17.136 15.498 17.28 ;
    END
  END o[170]
  PIN o[171]
    DIRECTION OUTPUT ;
    USE SIGNAL ;
    PORT
      LAYER M5 ;
        RECT  15.552 17.088 15.576 17.28 ;
    END
  END o[171]
  PIN o[172]
    DIRECTION OUTPUT ;
    USE SIGNAL ;
    PORT
      LAYER M3 ;
        RECT  15.66 17.136 15.678 17.28 ;
    END
  END o[172]
  PIN o[173]
    DIRECTION OUTPUT ;
    USE SIGNAL ;
    PORT
      LAYER M5 ;
        RECT  15.744 17.088 15.768 17.28 ;
    END
  END o[173]
  PIN o[174]
    DIRECTION OUTPUT ;
    USE SIGNAL ;
    PORT
      LAYER M3 ;
        RECT  15.804 17.136 15.822 17.28 ;
    END
  END o[174]
  PIN o[175]
    DIRECTION OUTPUT ;
    USE SIGNAL ;
    PORT
      LAYER M5 ;
        RECT  15.888 17.088 15.912 17.28 ;
    END
  END o[175]
  PIN o[176]
    DIRECTION OUTPUT ;
    USE SIGNAL ;
    PORT
      LAYER M3 ;
        RECT  15.948 17.136 15.966 17.28 ;
    END
  END o[176]
  PIN o[177]
    DIRECTION OUTPUT ;
    USE SIGNAL ;
    PORT
      LAYER M5 ;
        RECT  16.032 17.088 16.056 17.28 ;
    END
  END o[177]
  PIN o[178]
    DIRECTION OUTPUT ;
    USE SIGNAL ;
    PORT
      LAYER M3 ;
        RECT  16.128 17.136 16.146 17.28 ;
    END
  END o[178]
  PIN o[179]
    DIRECTION OUTPUT ;
    USE SIGNAL ;
    PORT
      LAYER M5 ;
        RECT  16.176 17.088 16.2 17.28 ;
    END
  END o[179]
  PIN o[17]
    DIRECTION OUTPUT ;
    USE SIGNAL ;
    PORT
      LAYER M5 ;
        RECT  3.504 17.088 3.528 17.28 ;
    END
  END o[17]
  PIN o[180]
    DIRECTION OUTPUT ;
    USE SIGNAL ;
    PORT
      LAYER M3 ;
        RECT  16.272 17.136 16.29 17.28 ;
    END
  END o[180]
  PIN o[181]
    DIRECTION OUTPUT ;
    USE SIGNAL ;
    PORT
      LAYER M5 ;
        RECT  16.368 17.088 16.392 17.28 ;
    END
  END o[181]
  PIN o[182]
    DIRECTION OUTPUT ;
    USE SIGNAL ;
    PORT
      LAYER M3 ;
        RECT  16.416 17.136 16.434 17.28 ;
    END
  END o[182]
  PIN o[183]
    DIRECTION OUTPUT ;
    USE SIGNAL ;
    PORT
      LAYER M5 ;
        RECT  16.512 17.088 16.536 17.28 ;
    END
  END o[183]
  PIN o[184]
    DIRECTION OUTPUT ;
    USE SIGNAL ;
    PORT
      LAYER M3 ;
        RECT  16.596 17.136 16.614 17.28 ;
    END
  END o[184]
  PIN o[185]
    DIRECTION OUTPUT ;
    USE SIGNAL ;
    PORT
      LAYER M5 ;
        RECT  16.656 17.088 16.68 17.28 ;
    END
  END o[185]
  PIN o[186]
    DIRECTION OUTPUT ;
    USE SIGNAL ;
    PORT
      LAYER M3 ;
        RECT  16.74 17.136 16.758 17.28 ;
    END
  END o[186]
  PIN o[187]
    DIRECTION OUTPUT ;
    USE SIGNAL ;
    PORT
      LAYER M5 ;
        RECT  16.8 17.088 16.824 17.28 ;
    END
  END o[187]
  PIN o[188]
    DIRECTION OUTPUT ;
    USE SIGNAL ;
    PORT
      LAYER M3 ;
        RECT  16.92 17.136 16.938 17.28 ;
    END
  END o[188]
  PIN o[189]
    DIRECTION OUTPUT ;
    USE SIGNAL ;
    PORT
      LAYER M5 ;
        RECT  16.992 17.088 17.016 17.28 ;
    END
  END o[189]
  PIN o[18]
    DIRECTION OUTPUT ;
    USE SIGNAL ;
    PORT
      LAYER M3 ;
        RECT  3.6 17.136 3.618 17.28 ;
    END
  END o[18]
  PIN o[190]
    DIRECTION OUTPUT ;
    USE SIGNAL ;
    PORT
      LAYER M3 ;
        RECT  17.064 17.136 17.082 17.28 ;
    END
  END o[190]
  PIN o[191]
    DIRECTION OUTPUT ;
    USE SIGNAL ;
    PORT
      LAYER M5 ;
        RECT  17.136 17.088 17.16 17.28 ;
    END
  END o[191]
  PIN o[192]
    DIRECTION OUTPUT ;
    USE SIGNAL ;
    PORT
      LAYER M3 ;
        RECT  17.208 17.136 17.226 17.28 ;
    END
  END o[192]
  PIN o[193]
    DIRECTION OUTPUT ;
    USE SIGNAL ;
    PORT
      LAYER M5 ;
        RECT  17.28 17.088 17.304 17.28 ;
    END
  END o[193]
  PIN o[194]
    DIRECTION OUTPUT ;
    USE SIGNAL ;
    PORT
      LAYER M3 ;
        RECT  17.388 17.136 17.406 17.28 ;
    END
  END o[194]
  PIN o[195]
    DIRECTION OUTPUT ;
    USE SIGNAL ;
    PORT
      LAYER M5 ;
        RECT  17.472 17.088 17.496 17.28 ;
    END
  END o[195]
  PIN o[196]
    DIRECTION OUTPUT ;
    USE SIGNAL ;
    PORT
      LAYER M3 ;
        RECT  17.532 17.136 17.55 17.28 ;
    END
  END o[196]
  PIN o[197]
    DIRECTION OUTPUT ;
    USE SIGNAL ;
    PORT
      LAYER M5 ;
        RECT  17.616 17.088 17.64 17.28 ;
    END
  END o[197]
  PIN o[198]
    DIRECTION OUTPUT ;
    USE SIGNAL ;
    PORT
      LAYER M3 ;
        RECT  17.676 17.136 17.694 17.28 ;
    END
  END o[198]
  PIN o[199]
    DIRECTION OUTPUT ;
    USE SIGNAL ;
    PORT
      LAYER M5 ;
        RECT  17.76 17.088 17.784 17.28 ;
    END
  END o[199]
  PIN o[19]
    DIRECTION OUTPUT ;
    USE SIGNAL ;
    PORT
      LAYER M5 ;
        RECT  3.696 17.088 3.72 17.28 ;
    END
  END o[19]
  PIN o[1]
    DIRECTION OUTPUT ;
    USE SIGNAL ;
    PORT
      LAYER M5 ;
        RECT  2.256 17.088 2.28 17.28 ;
    END
  END o[1]
  PIN o[200]
    DIRECTION OUTPUT ;
    USE SIGNAL ;
    PORT
      LAYER M3 ;
        RECT  17.856 17.136 17.874 17.28 ;
    END
  END o[200]
  PIN o[201]
    DIRECTION OUTPUT ;
    USE SIGNAL ;
    PORT
      LAYER M5 ;
        RECT  17.904 17.088 17.928 17.28 ;
    END
  END o[201]
  PIN o[202]
    DIRECTION OUTPUT ;
    USE SIGNAL ;
    PORT
      LAYER M3 ;
        RECT  18 17.136 18.018 17.28 ;
    END
  END o[202]
  PIN o[203]
    DIRECTION OUTPUT ;
    USE SIGNAL ;
    PORT
      LAYER M5 ;
        RECT  18.096 17.088 18.12 17.28 ;
    END
  END o[203]
  PIN o[204]
    DIRECTION OUTPUT ;
    USE SIGNAL ;
    PORT
      LAYER M3 ;
        RECT  18.144 17.136 18.162 17.28 ;
    END
  END o[204]
  PIN o[205]
    DIRECTION OUTPUT ;
    USE SIGNAL ;
    PORT
      LAYER M5 ;
        RECT  18.24 17.088 18.264 17.28 ;
    END
  END o[205]
  PIN o[206]
    DIRECTION OUTPUT ;
    USE SIGNAL ;
    PORT
      LAYER M3 ;
        RECT  18.324 17.136 18.342 17.28 ;
    END
  END o[206]
  PIN o[207]
    DIRECTION OUTPUT ;
    USE SIGNAL ;
    PORT
      LAYER M5 ;
        RECT  18.384 17.088 18.408 17.28 ;
    END
  END o[207]
  PIN o[208]
    DIRECTION OUTPUT ;
    USE SIGNAL ;
    PORT
      LAYER M3 ;
        RECT  18.468 17.136 18.486 17.28 ;
    END
  END o[208]
  PIN o[209]
    DIRECTION OUTPUT ;
    USE SIGNAL ;
    PORT
      LAYER M5 ;
        RECT  18.528 17.088 18.552 17.28 ;
    END
  END o[209]
  PIN o[20]
    DIRECTION OUTPUT ;
    USE SIGNAL ;
    PORT
      LAYER M3 ;
        RECT  3.744 17.136 3.762 17.28 ;
    END
  END o[20]
  PIN o[210]
    DIRECTION OUTPUT ;
    USE SIGNAL ;
    PORT
      LAYER M3 ;
        RECT  18.612 17.136 18.63 17.28 ;
    END
  END o[210]
  PIN o[211]
    DIRECTION OUTPUT ;
    USE SIGNAL ;
    PORT
      LAYER M5 ;
        RECT  18.72 17.088 18.744 17.28 ;
    END
  END o[211]
  PIN o[212]
    DIRECTION OUTPUT ;
    USE SIGNAL ;
    PORT
      LAYER M3 ;
        RECT  18.792 17.136 18.81 17.28 ;
    END
  END o[212]
  PIN o[213]
    DIRECTION OUTPUT ;
    USE SIGNAL ;
    PORT
      LAYER M5 ;
        RECT  18.864 17.088 18.888 17.28 ;
    END
  END o[213]
  PIN o[214]
    DIRECTION OUTPUT ;
    USE SIGNAL ;
    PORT
      LAYER M3 ;
        RECT  18.936 17.136 18.954 17.28 ;
    END
  END o[214]
  PIN o[215]
    DIRECTION OUTPUT ;
    USE SIGNAL ;
    PORT
      LAYER M5 ;
        RECT  19.008 17.088 19.032 17.28 ;
    END
  END o[215]
  PIN o[216]
    DIRECTION OUTPUT ;
    USE SIGNAL ;
    PORT
      LAYER M3 ;
        RECT  19.08 17.136 19.098 17.28 ;
    END
  END o[216]
  PIN o[217]
    DIRECTION OUTPUT ;
    USE SIGNAL ;
    PORT
      LAYER M5 ;
        RECT  19.152 17.088 19.176 17.28 ;
    END
  END o[217]
  PIN o[218]
    DIRECTION OUTPUT ;
    USE SIGNAL ;
    PORT
      LAYER M3 ;
        RECT  19.26 17.136 19.278 17.28 ;
    END
  END o[218]
  PIN o[219]
    DIRECTION OUTPUT ;
    USE SIGNAL ;
    PORT
      LAYER M5 ;
        RECT  19.344 17.088 19.368 17.28 ;
    END
  END o[219]
  PIN o[21]
    DIRECTION OUTPUT ;
    USE SIGNAL ;
    PORT
      LAYER M5 ;
        RECT  3.84 17.088 3.864 17.28 ;
    END
  END o[21]
  PIN o[220]
    DIRECTION OUTPUT ;
    USE SIGNAL ;
    PORT
      LAYER M3 ;
        RECT  19.404 17.136 19.422 17.28 ;
    END
  END o[220]
  PIN o[221]
    DIRECTION OUTPUT ;
    USE SIGNAL ;
    PORT
      LAYER M5 ;
        RECT  19.488 17.088 19.512 17.28 ;
    END
  END o[221]
  PIN o[222]
    DIRECTION OUTPUT ;
    USE SIGNAL ;
    PORT
      LAYER M3 ;
        RECT  19.548 17.136 19.566 17.28 ;
    END
  END o[222]
  PIN o[223]
    DIRECTION OUTPUT ;
    USE SIGNAL ;
    PORT
      LAYER M5 ;
        RECT  19.632 17.088 19.656 17.28 ;
    END
  END o[223]
  PIN o[224]
    DIRECTION OUTPUT ;
    USE SIGNAL ;
    PORT
      LAYER M3 ;
        RECT  19.728 17.136 19.746 17.28 ;
    END
  END o[224]
  PIN o[225]
    DIRECTION OUTPUT ;
    USE SIGNAL ;
    PORT
      LAYER M5 ;
        RECT  19.776 17.088 19.8 17.28 ;
    END
  END o[225]
  PIN o[226]
    DIRECTION OUTPUT ;
    USE SIGNAL ;
    PORT
      LAYER M3 ;
        RECT  19.872 17.136 19.89 17.28 ;
    END
  END o[226]
  PIN o[227]
    DIRECTION OUTPUT ;
    USE SIGNAL ;
    PORT
      LAYER M5 ;
        RECT  19.968 17.088 19.992 17.28 ;
    END
  END o[227]
  PIN o[228]
    DIRECTION OUTPUT ;
    USE SIGNAL ;
    PORT
      LAYER M3 ;
        RECT  20.016 17.136 20.034 17.28 ;
    END
  END o[228]
  PIN o[229]
    DIRECTION OUTPUT ;
    USE SIGNAL ;
    PORT
      LAYER M5 ;
        RECT  20.112 17.088 20.136 17.28 ;
    END
  END o[229]
  PIN o[22]
    DIRECTION OUTPUT ;
    USE SIGNAL ;
    PORT
      LAYER M3 ;
        RECT  3.924 17.136 3.942 17.28 ;
    END
  END o[22]
  PIN o[230]
    DIRECTION OUTPUT ;
    USE SIGNAL ;
    PORT
      LAYER M3 ;
        RECT  20.196 17.136 20.214 17.28 ;
    END
  END o[230]
  PIN o[231]
    DIRECTION OUTPUT ;
    USE SIGNAL ;
    PORT
      LAYER M5 ;
        RECT  20.256 17.088 20.28 17.28 ;
    END
  END o[231]
  PIN o[232]
    DIRECTION OUTPUT ;
    USE SIGNAL ;
    PORT
      LAYER M3 ;
        RECT  20.34 17.136 20.358 17.28 ;
    END
  END o[232]
  PIN o[233]
    DIRECTION OUTPUT ;
    USE SIGNAL ;
    PORT
      LAYER M5 ;
        RECT  20.4 17.088 20.424 17.28 ;
    END
  END o[233]
  PIN o[234]
    DIRECTION OUTPUT ;
    USE SIGNAL ;
    PORT
      LAYER M3 ;
        RECT  20.52 17.136 20.538 17.28 ;
    END
  END o[234]
  PIN o[235]
    DIRECTION OUTPUT ;
    USE SIGNAL ;
    PORT
      LAYER M5 ;
        RECT  20.592 17.088 20.616 17.28 ;
    END
  END o[235]
  PIN o[236]
    DIRECTION OUTPUT ;
    USE SIGNAL ;
    PORT
      LAYER M3 ;
        RECT  20.664 17.136 20.682 17.28 ;
    END
  END o[236]
  PIN o[237]
    DIRECTION OUTPUT ;
    USE SIGNAL ;
    PORT
      LAYER M5 ;
        RECT  20.736 17.088 20.76 17.28 ;
    END
  END o[237]
  PIN o[238]
    DIRECTION OUTPUT ;
    USE SIGNAL ;
    PORT
      LAYER M3 ;
        RECT  20.808 17.136 20.826 17.28 ;
    END
  END o[238]
  PIN o[239]
    DIRECTION OUTPUT ;
    USE SIGNAL ;
    PORT
      LAYER M5 ;
        RECT  20.88 17.088 20.904 17.28 ;
    END
  END o[239]
  PIN o[23]
    DIRECTION OUTPUT ;
    USE SIGNAL ;
    PORT
      LAYER M5 ;
        RECT  3.984 17.088 4.008 17.28 ;
    END
  END o[23]
  PIN o[240]
    DIRECTION OUTPUT ;
    USE SIGNAL ;
    PORT
      LAYER M3 ;
        RECT  20.988 17.136 21.006 17.28 ;
    END
  END o[240]
  PIN o[241]
    DIRECTION OUTPUT ;
    USE SIGNAL ;
    PORT
      LAYER M5 ;
        RECT  21.072 17.088 21.096 17.28 ;
    END
  END o[241]
  PIN o[242]
    DIRECTION OUTPUT ;
    USE SIGNAL ;
    PORT
      LAYER M3 ;
        RECT  21.132 17.136 21.15 17.28 ;
    END
  END o[242]
  PIN o[243]
    DIRECTION OUTPUT ;
    USE SIGNAL ;
    PORT
      LAYER M5 ;
        RECT  21.216 17.088 21.24 17.28 ;
    END
  END o[243]
  PIN o[244]
    DIRECTION OUTPUT ;
    USE SIGNAL ;
    PORT
      LAYER M3 ;
        RECT  21.276 17.136 21.294 17.28 ;
    END
  END o[244]
  PIN o[245]
    DIRECTION OUTPUT ;
    USE SIGNAL ;
    PORT
      LAYER M5 ;
        RECT  21.36 17.088 21.384 17.28 ;
    END
  END o[245]
  PIN o[246]
    DIRECTION OUTPUT ;
    USE SIGNAL ;
    PORT
      LAYER M3 ;
        RECT  21.456 17.136 21.474 17.28 ;
    END
  END o[246]
  PIN o[247]
    DIRECTION OUTPUT ;
    USE SIGNAL ;
    PORT
      LAYER M5 ;
        RECT  21.504 17.088 21.528 17.28 ;
    END
  END o[247]
  PIN o[248]
    DIRECTION OUTPUT ;
    USE SIGNAL ;
    PORT
      LAYER M3 ;
        RECT  21.6 17.136 21.618 17.28 ;
    END
  END o[248]
  PIN o[249]
    DIRECTION OUTPUT ;
    USE SIGNAL ;
    PORT
      LAYER M5 ;
        RECT  21.696 17.088 21.72 17.28 ;
    END
  END o[249]
  PIN o[24]
    DIRECTION OUTPUT ;
    USE SIGNAL ;
    PORT
      LAYER M3 ;
        RECT  4.068 17.136 4.086 17.28 ;
    END
  END o[24]
  PIN o[250]
    DIRECTION OUTPUT ;
    USE SIGNAL ;
    PORT
      LAYER M3 ;
        RECT  21.744 17.136 21.762 17.28 ;
    END
  END o[250]
  PIN o[251]
    DIRECTION OUTPUT ;
    USE SIGNAL ;
    PORT
      LAYER M5 ;
        RECT  21.84 17.088 21.864 17.28 ;
    END
  END o[251]
  PIN o[252]
    DIRECTION OUTPUT ;
    USE SIGNAL ;
    PORT
      LAYER M3 ;
        RECT  21.924 17.136 21.942 17.28 ;
    END
  END o[252]
  PIN o[253]
    DIRECTION OUTPUT ;
    USE SIGNAL ;
    PORT
      LAYER M5 ;
        RECT  21.984 17.088 22.008 17.28 ;
    END
  END o[253]
  PIN o[254]
    DIRECTION OUTPUT ;
    USE SIGNAL ;
    PORT
      LAYER M3 ;
        RECT  22.068 17.136 22.086 17.28 ;
    END
  END o[254]
  PIN o[255]
    DIRECTION OUTPUT ;
    USE SIGNAL ;
    PORT
      LAYER M5 ;
        RECT  22.128 17.088 22.152 17.28 ;
    END
  END o[255]
  PIN o[256]
    DIRECTION OUTPUT ;
    USE SIGNAL ;
    PORT
      LAYER M3 ;
        RECT  22.212 17.136 22.23 17.28 ;
    END
  END o[256]
  PIN o[257]
    DIRECTION OUTPUT ;
    USE SIGNAL ;
    PORT
      LAYER M5 ;
        RECT  22.32 17.088 22.344 17.28 ;
    END
  END o[257]
  PIN o[258]
    DIRECTION OUTPUT ;
    USE SIGNAL ;
    PORT
      LAYER M3 ;
        RECT  22.392 17.136 22.41 17.28 ;
    END
  END o[258]
  PIN o[259]
    DIRECTION OUTPUT ;
    USE SIGNAL ;
    PORT
      LAYER M5 ;
        RECT  22.464 17.088 22.488 17.28 ;
    END
  END o[259]
  PIN o[25]
    DIRECTION OUTPUT ;
    USE SIGNAL ;
    PORT
      LAYER M5 ;
        RECT  4.128 17.088 4.152 17.28 ;
    END
  END o[25]
  PIN o[260]
    DIRECTION OUTPUT ;
    USE SIGNAL ;
    PORT
      LAYER M3 ;
        RECT  22.536 17.136 22.554 17.28 ;
    END
  END o[260]
  PIN o[261]
    DIRECTION OUTPUT ;
    USE SIGNAL ;
    PORT
      LAYER M5 ;
        RECT  22.608 17.088 22.632 17.28 ;
    END
  END o[261]
  PIN o[262]
    DIRECTION OUTPUT ;
    USE SIGNAL ;
    PORT
      LAYER M3 ;
        RECT  22.68 17.136 22.698 17.28 ;
    END
  END o[262]
  PIN o[263]
    DIRECTION OUTPUT ;
    USE SIGNAL ;
    PORT
      LAYER M5 ;
        RECT  22.752 17.088 22.776 17.28 ;
    END
  END o[263]
  PIN o[264]
    DIRECTION OUTPUT ;
    USE SIGNAL ;
    PORT
      LAYER M3 ;
        RECT  22.86 17.136 22.878 17.28 ;
    END
  END o[264]
  PIN o[265]
    DIRECTION OUTPUT ;
    USE SIGNAL ;
    PORT
      LAYER M5 ;
        RECT  22.944 17.088 22.968 17.28 ;
    END
  END o[265]
  PIN o[266]
    DIRECTION OUTPUT ;
    USE SIGNAL ;
    PORT
      LAYER M3 ;
        RECT  23.004 17.136 23.022 17.28 ;
    END
  END o[266]
  PIN o[267]
    DIRECTION OUTPUT ;
    USE SIGNAL ;
    PORT
      LAYER M5 ;
        RECT  23.088 17.088 23.112 17.28 ;
    END
  END o[267]
  PIN o[268]
    DIRECTION OUTPUT ;
    USE SIGNAL ;
    PORT
      LAYER M3 ;
        RECT  23.148 17.136 23.166 17.28 ;
    END
  END o[268]
  PIN o[269]
    DIRECTION OUTPUT ;
    USE SIGNAL ;
    PORT
      LAYER M5 ;
        RECT  23.232 17.088 23.256 17.28 ;
    END
  END o[269]
  PIN o[26]
    DIRECTION OUTPUT ;
    USE SIGNAL ;
    PORT
      LAYER M3 ;
        RECT  4.212 17.136 4.23 17.28 ;
    END
  END o[26]
  PIN o[270]
    DIRECTION OUTPUT ;
    USE SIGNAL ;
    PORT
      LAYER M3 ;
        RECT  23.328 17.136 23.346 17.28 ;
    END
  END o[270]
  PIN o[271]
    DIRECTION OUTPUT ;
    USE SIGNAL ;
    PORT
      LAYER M5 ;
        RECT  23.376 17.088 23.4 17.28 ;
    END
  END o[271]
  PIN o[272]
    DIRECTION OUTPUT ;
    USE SIGNAL ;
    PORT
      LAYER M3 ;
        RECT  23.472 17.136 23.49 17.28 ;
    END
  END o[272]
  PIN o[273]
    DIRECTION OUTPUT ;
    USE SIGNAL ;
    PORT
      LAYER M5 ;
        RECT  23.568 17.088 23.592 17.28 ;
    END
  END o[273]
  PIN o[274]
    DIRECTION OUTPUT ;
    USE SIGNAL ;
    PORT
      LAYER M3 ;
        RECT  23.616 17.136 23.634 17.28 ;
    END
  END o[274]
  PIN o[275]
    DIRECTION OUTPUT ;
    USE SIGNAL ;
    PORT
      LAYER M5 ;
        RECT  23.712 17.088 23.736 17.28 ;
    END
  END o[275]
  PIN o[27]
    DIRECTION OUTPUT ;
    USE SIGNAL ;
    PORT
      LAYER M5 ;
        RECT  4.32 17.088 4.344 17.28 ;
    END
  END o[27]
  PIN o[28]
    DIRECTION OUTPUT ;
    USE SIGNAL ;
    PORT
      LAYER M3 ;
        RECT  4.392 17.136 4.41 17.28 ;
    END
  END o[28]
  PIN o[29]
    DIRECTION OUTPUT ;
    USE SIGNAL ;
    PORT
      LAYER M5 ;
        RECT  4.464 17.088 4.488 17.28 ;
    END
  END o[29]
  PIN o[2]
    DIRECTION OUTPUT ;
    USE SIGNAL ;
    PORT
      LAYER M3 ;
        RECT  2.34 17.136 2.358 17.28 ;
    END
  END o[2]
  PIN o[30]
    DIRECTION OUTPUT ;
    USE SIGNAL ;
    PORT
      LAYER M3 ;
        RECT  4.536 17.136 4.554 17.28 ;
    END
  END o[30]
  PIN o[31]
    DIRECTION OUTPUT ;
    USE SIGNAL ;
    PORT
      LAYER M5 ;
        RECT  4.608 17.088 4.632 17.28 ;
    END
  END o[31]
  PIN o[32]
    DIRECTION OUTPUT ;
    USE SIGNAL ;
    PORT
      LAYER M3 ;
        RECT  4.68 17.136 4.698 17.28 ;
    END
  END o[32]
  PIN o[33]
    DIRECTION OUTPUT ;
    USE SIGNAL ;
    PORT
      LAYER M5 ;
        RECT  4.752 17.088 4.776 17.28 ;
    END
  END o[33]
  PIN o[34]
    DIRECTION OUTPUT ;
    USE SIGNAL ;
    PORT
      LAYER M3 ;
        RECT  4.86 17.136 4.878 17.28 ;
    END
  END o[34]
  PIN o[35]
    DIRECTION OUTPUT ;
    USE SIGNAL ;
    PORT
      LAYER M5 ;
        RECT  4.944 17.088 4.968 17.28 ;
    END
  END o[35]
  PIN o[36]
    DIRECTION OUTPUT ;
    USE SIGNAL ;
    PORT
      LAYER M3 ;
        RECT  5.004 17.136 5.022 17.28 ;
    END
  END o[36]
  PIN o[37]
    DIRECTION OUTPUT ;
    USE SIGNAL ;
    PORT
      LAYER M5 ;
        RECT  5.088 17.088 5.112 17.28 ;
    END
  END o[37]
  PIN o[38]
    DIRECTION OUTPUT ;
    USE SIGNAL ;
    PORT
      LAYER M3 ;
        RECT  5.148 17.136 5.166 17.28 ;
    END
  END o[38]
  PIN o[39]
    DIRECTION OUTPUT ;
    USE SIGNAL ;
    PORT
      LAYER M5 ;
        RECT  5.232 17.088 5.256 17.28 ;
    END
  END o[39]
  PIN o[3]
    DIRECTION OUTPUT ;
    USE SIGNAL ;
    PORT
      LAYER M5 ;
        RECT  2.4 17.088 2.424 17.28 ;
    END
  END o[3]
  PIN o[40]
    DIRECTION OUTPUT ;
    USE SIGNAL ;
    PORT
      LAYER M3 ;
        RECT  5.328 17.136 5.346 17.28 ;
    END
  END o[40]
  PIN o[41]
    DIRECTION OUTPUT ;
    USE SIGNAL ;
    PORT
      LAYER M5 ;
        RECT  5.376 17.088 5.4 17.28 ;
    END
  END o[41]
  PIN o[42]
    DIRECTION OUTPUT ;
    USE SIGNAL ;
    PORT
      LAYER M3 ;
        RECT  5.472 17.136 5.49 17.28 ;
    END
  END o[42]
  PIN o[43]
    DIRECTION OUTPUT ;
    USE SIGNAL ;
    PORT
      LAYER M5 ;
        RECT  5.568 17.088 5.592 17.28 ;
    END
  END o[43]
  PIN o[44]
    DIRECTION OUTPUT ;
    USE SIGNAL ;
    PORT
      LAYER M3 ;
        RECT  5.616 17.136 5.634 17.28 ;
    END
  END o[44]
  PIN o[45]
    DIRECTION OUTPUT ;
    USE SIGNAL ;
    PORT
      LAYER M5 ;
        RECT  5.712 17.088 5.736 17.28 ;
    END
  END o[45]
  PIN o[46]
    DIRECTION OUTPUT ;
    USE SIGNAL ;
    PORT
      LAYER M3 ;
        RECT  5.796 17.136 5.814 17.28 ;
    END
  END o[46]
  PIN o[47]
    DIRECTION OUTPUT ;
    USE SIGNAL ;
    PORT
      LAYER M5 ;
        RECT  5.856 17.088 5.88 17.28 ;
    END
  END o[47]
  PIN o[48]
    DIRECTION OUTPUT ;
    USE SIGNAL ;
    PORT
      LAYER M3 ;
        RECT  5.94 17.136 5.958 17.28 ;
    END
  END o[48]
  PIN o[49]
    DIRECTION OUTPUT ;
    USE SIGNAL ;
    PORT
      LAYER M5 ;
        RECT  6 17.088 6.024 17.28 ;
    END
  END o[49]
  PIN o[4]
    DIRECTION OUTPUT ;
    USE SIGNAL ;
    PORT
      LAYER M3 ;
        RECT  2.52 17.136 2.538 17.28 ;
    END
  END o[4]
  PIN o[50]
    DIRECTION OUTPUT ;
    USE SIGNAL ;
    PORT
      LAYER M3 ;
        RECT  6.12 17.136 6.138 17.28 ;
    END
  END o[50]
  PIN o[51]
    DIRECTION OUTPUT ;
    USE SIGNAL ;
    PORT
      LAYER M5 ;
        RECT  6.192 17.088 6.216 17.28 ;
    END
  END o[51]
  PIN o[52]
    DIRECTION OUTPUT ;
    USE SIGNAL ;
    PORT
      LAYER M3 ;
        RECT  6.264 17.136 6.282 17.28 ;
    END
  END o[52]
  PIN o[53]
    DIRECTION OUTPUT ;
    USE SIGNAL ;
    PORT
      LAYER M5 ;
        RECT  6.336 17.088 6.36 17.28 ;
    END
  END o[53]
  PIN o[54]
    DIRECTION OUTPUT ;
    USE SIGNAL ;
    PORT
      LAYER M3 ;
        RECT  6.408 17.136 6.426 17.28 ;
    END
  END o[54]
  PIN o[55]
    DIRECTION OUTPUT ;
    USE SIGNAL ;
    PORT
      LAYER M5 ;
        RECT  6.48 17.088 6.504 17.28 ;
    END
  END o[55]
  PIN o[56]
    DIRECTION OUTPUT ;
    USE SIGNAL ;
    PORT
      LAYER M3 ;
        RECT  6.588 17.136 6.606 17.28 ;
    END
  END o[56]
  PIN o[57]
    DIRECTION OUTPUT ;
    USE SIGNAL ;
    PORT
      LAYER M5 ;
        RECT  6.624 17.088 6.648 17.28 ;
    END
  END o[57]
  PIN o[58]
    DIRECTION OUTPUT ;
    USE SIGNAL ;
    PORT
      LAYER M3 ;
        RECT  6.732 17.136 6.75 17.28 ;
    END
  END o[58]
  PIN o[59]
    DIRECTION OUTPUT ;
    USE SIGNAL ;
    PORT
      LAYER M5 ;
        RECT  6.816 17.088 6.84 17.28 ;
    END
  END o[59]
  PIN o[5]
    DIRECTION OUTPUT ;
    USE SIGNAL ;
    PORT
      LAYER M5 ;
        RECT  2.592 17.088 2.616 17.28 ;
    END
  END o[5]
  PIN o[60]
    DIRECTION OUTPUT ;
    USE SIGNAL ;
    PORT
      LAYER M3 ;
        RECT  6.876 17.136 6.894 17.28 ;
    END
  END o[60]
  PIN o[61]
    DIRECTION OUTPUT ;
    USE SIGNAL ;
    PORT
      LAYER M5 ;
        RECT  6.96 17.088 6.984 17.28 ;
    END
  END o[61]
  PIN o[62]
    DIRECTION OUTPUT ;
    USE SIGNAL ;
    PORT
      LAYER M3 ;
        RECT  7.056 17.136 7.074 17.28 ;
    END
  END o[62]
  PIN o[63]
    DIRECTION OUTPUT ;
    USE SIGNAL ;
    PORT
      LAYER M5 ;
        RECT  7.104 17.088 7.128 17.28 ;
    END
  END o[63]
  PIN o[64]
    DIRECTION OUTPUT ;
    USE SIGNAL ;
    PORT
      LAYER M3 ;
        RECT  7.2 17.136 7.218 17.28 ;
    END
  END o[64]
  PIN o[65]
    DIRECTION OUTPUT ;
    USE SIGNAL ;
    PORT
      LAYER M5 ;
        RECT  7.296 17.088 7.32 17.28 ;
    END
  END o[65]
  PIN o[66]
    DIRECTION OUTPUT ;
    USE SIGNAL ;
    PORT
      LAYER M3 ;
        RECT  7.344 17.136 7.362 17.28 ;
    END
  END o[66]
  PIN o[67]
    DIRECTION OUTPUT ;
    USE SIGNAL ;
    PORT
      LAYER M5 ;
        RECT  7.44 17.088 7.464 17.28 ;
    END
  END o[67]
  PIN o[68]
    DIRECTION OUTPUT ;
    USE SIGNAL ;
    PORT
      LAYER M3 ;
        RECT  7.524 17.136 7.542 17.28 ;
    END
  END o[68]
  PIN o[69]
    DIRECTION OUTPUT ;
    USE SIGNAL ;
    PORT
      LAYER M5 ;
        RECT  7.584 17.088 7.608 17.28 ;
    END
  END o[69]
  PIN o[6]
    DIRECTION OUTPUT ;
    USE SIGNAL ;
    PORT
      LAYER M3 ;
        RECT  2.664 17.136 2.682 17.28 ;
    END
  END o[6]
  PIN o[70]
    DIRECTION OUTPUT ;
    USE SIGNAL ;
    PORT
      LAYER M3 ;
        RECT  7.668 17.136 7.686 17.28 ;
    END
  END o[70]
  PIN o[71]
    DIRECTION OUTPUT ;
    USE SIGNAL ;
    PORT
      LAYER M5 ;
        RECT  7.728 17.088 7.752 17.28 ;
    END
  END o[71]
  PIN o[72]
    DIRECTION OUTPUT ;
    USE SIGNAL ;
    PORT
      LAYER M3 ;
        RECT  7.812 17.136 7.83 17.28 ;
    END
  END o[72]
  PIN o[73]
    DIRECTION OUTPUT ;
    USE SIGNAL ;
    PORT
      LAYER M5 ;
        RECT  7.92 17.088 7.944 17.28 ;
    END
  END o[73]
  PIN o[74]
    DIRECTION OUTPUT ;
    USE SIGNAL ;
    PORT
      LAYER M3 ;
        RECT  7.992 17.136 8.01 17.28 ;
    END
  END o[74]
  PIN o[75]
    DIRECTION OUTPUT ;
    USE SIGNAL ;
    PORT
      LAYER M5 ;
        RECT  8.064 17.088 8.088 17.28 ;
    END
  END o[75]
  PIN o[76]
    DIRECTION OUTPUT ;
    USE SIGNAL ;
    PORT
      LAYER M3 ;
        RECT  8.136 17.136 8.154 17.28 ;
    END
  END o[76]
  PIN o[77]
    DIRECTION OUTPUT ;
    USE SIGNAL ;
    PORT
      LAYER M5 ;
        RECT  8.208 17.088 8.232 17.28 ;
    END
  END o[77]
  PIN o[78]
    DIRECTION OUTPUT ;
    USE SIGNAL ;
    PORT
      LAYER M3 ;
        RECT  8.28 17.136 8.298 17.28 ;
    END
  END o[78]
  PIN o[79]
    DIRECTION OUTPUT ;
    USE SIGNAL ;
    PORT
      LAYER M5 ;
        RECT  8.352 17.088 8.376 17.28 ;
    END
  END o[79]
  PIN o[7]
    DIRECTION OUTPUT ;
    USE SIGNAL ;
    PORT
      LAYER M5 ;
        RECT  2.736 17.088 2.76 17.28 ;
    END
  END o[7]
  PIN o[80]
    DIRECTION OUTPUT ;
    USE SIGNAL ;
    PORT
      LAYER M3 ;
        RECT  8.46 17.136 8.478 17.28 ;
    END
  END o[80]
  PIN o[81]
    DIRECTION OUTPUT ;
    USE SIGNAL ;
    PORT
      LAYER M5 ;
        RECT  8.544 17.088 8.568 17.28 ;
    END
  END o[81]
  PIN o[82]
    DIRECTION OUTPUT ;
    USE SIGNAL ;
    PORT
      LAYER M3 ;
        RECT  8.604 17.136 8.622 17.28 ;
    END
  END o[82]
  PIN o[83]
    DIRECTION OUTPUT ;
    USE SIGNAL ;
    PORT
      LAYER M5 ;
        RECT  8.688 17.088 8.712 17.28 ;
    END
  END o[83]
  PIN o[84]
    DIRECTION OUTPUT ;
    USE SIGNAL ;
    PORT
      LAYER M3 ;
        RECT  8.748 17.136 8.766 17.28 ;
    END
  END o[84]
  PIN o[85]
    DIRECTION OUTPUT ;
    USE SIGNAL ;
    PORT
      LAYER M5 ;
        RECT  8.832 17.088 8.856 17.28 ;
    END
  END o[85]
  PIN o[86]
    DIRECTION OUTPUT ;
    USE SIGNAL ;
    PORT
      LAYER M3 ;
        RECT  8.928 17.136 8.946 17.28 ;
    END
  END o[86]
  PIN o[87]
    DIRECTION OUTPUT ;
    USE SIGNAL ;
    PORT
      LAYER M5 ;
        RECT  8.976 17.088 9 17.28 ;
    END
  END o[87]
  PIN o[88]
    DIRECTION OUTPUT ;
    USE SIGNAL ;
    PORT
      LAYER M3 ;
        RECT  9.072 17.136 9.09 17.28 ;
    END
  END o[88]
  PIN o[89]
    DIRECTION OUTPUT ;
    USE SIGNAL ;
    PORT
      LAYER M5 ;
        RECT  9.168 17.088 9.192 17.28 ;
    END
  END o[89]
  PIN o[8]
    DIRECTION OUTPUT ;
    USE SIGNAL ;
    PORT
      LAYER M3 ;
        RECT  2.808 17.136 2.826 17.28 ;
    END
  END o[8]
  PIN o[90]
    DIRECTION OUTPUT ;
    USE SIGNAL ;
    PORT
      LAYER M3 ;
        RECT  9.216 17.136 9.234 17.28 ;
    END
  END o[90]
  PIN o[91]
    DIRECTION OUTPUT ;
    USE SIGNAL ;
    PORT
      LAYER M5 ;
        RECT  9.312 17.088 9.336 17.28 ;
    END
  END o[91]
  PIN o[92]
    DIRECTION OUTPUT ;
    USE SIGNAL ;
    PORT
      LAYER M3 ;
        RECT  9.396 17.136 9.414 17.28 ;
    END
  END o[92]
  PIN o[93]
    DIRECTION OUTPUT ;
    USE SIGNAL ;
    PORT
      LAYER M5 ;
        RECT  9.456 17.088 9.48 17.28 ;
    END
  END o[93]
  PIN o[94]
    DIRECTION OUTPUT ;
    USE SIGNAL ;
    PORT
      LAYER M3 ;
        RECT  9.54 17.136 9.558 17.28 ;
    END
  END o[94]
  PIN o[95]
    DIRECTION OUTPUT ;
    USE SIGNAL ;
    PORT
      LAYER M5 ;
        RECT  9.6 17.088 9.624 17.28 ;
    END
  END o[95]
  PIN o[96]
    DIRECTION OUTPUT ;
    USE SIGNAL ;
    PORT
      LAYER M3 ;
        RECT  9.72 17.136 9.738 17.28 ;
    END
  END o[96]
  PIN o[97]
    DIRECTION OUTPUT ;
    USE SIGNAL ;
    PORT
      LAYER M5 ;
        RECT  9.792 17.088 9.816 17.28 ;
    END
  END o[97]
  PIN o[98]
    DIRECTION OUTPUT ;
    USE SIGNAL ;
    PORT
      LAYER M3 ;
        RECT  9.864 17.136 9.882 17.28 ;
    END
  END o[98]
  PIN o[99]
    DIRECTION OUTPUT ;
    USE SIGNAL ;
    PORT
      LAYER M5 ;
        RECT  9.936 17.088 9.96 17.28 ;
    END
  END o[99]
  PIN o[9]
    DIRECTION OUTPUT ;
    USE SIGNAL ;
    PORT
      LAYER M5 ;
        RECT  2.88 17.088 2.904 17.28 ;
    END
  END o[9]
  PIN rs
    DIRECTION INPUT ;
    USE SIGNAL ;
    PORT
      LAYER M4 ;
        RECT  25.728 11.904 25.92 11.928 ;
    END
  END rs
  PIN VDD
    DIRECTION INOUT ;
    USE POWER ;
    PORT
      LAYER M5 ;
        RECT  21.492 2.151 21.612 15.129 ;
        RECT  18.792 2.151 18.912 15.129 ;
        RECT  16.092 2.151 16.212 15.129 ;
        RECT  13.392 2.151 13.512 15.129 ;
        RECT  10.692 2.151 10.812 15.129 ;
        RECT  7.992 2.151 8.112 15.129 ;
        RECT  5.292 2.151 5.412 15.129 ;
        RECT  2.592 2.151 2.712 15.129 ;
    END
  END VDD
  PIN VSS
    DIRECTION INOUT ;
    USE GROUND ;
    PORT
      LAYER M5 ;
        RECT  21.3 2.137 21.42 15.143 ;
        RECT  18.6 2.137 18.72 15.143 ;
        RECT  15.9 2.137 16.02 15.143 ;
        RECT  13.2 2.137 13.32 15.143 ;
        RECT  10.5 2.137 10.62 15.143 ;
        RECT  7.8 2.137 7.92 15.143 ;
        RECT  5.1 2.137 5.22 15.143 ;
        RECT  2.4 2.137 2.52 15.143 ;
    END
  END VSS
  OBS
    LAYER RVTN ;
     RECT  2.16 2.16 23.76 2.295 ;
     RECT  2.16 2.565 23.76 2.835 ;
     RECT  2.16 3.105 23.76 3.375 ;
     RECT  2.16 3.645 23.76 3.915 ;
     RECT  2.16 4.185 23.76 4.455 ;
     RECT  2.16 4.725 23.76 4.995 ;
     RECT  2.16 5.265 23.76 5.535 ;
     RECT  2.16 5.805 23.76 6.075 ;
     RECT  2.16 6.345 23.76 6.615 ;
     RECT  2.16 6.885 23.76 7.155 ;
     RECT  2.16 7.425 23.76 7.695 ;
     RECT  2.16 7.965 23.76 8.235 ;
     RECT  2.16 8.505 23.76 8.775 ;
     RECT  2.16 9.045 23.76 9.315 ;
     RECT  2.16 9.585 23.76 9.855 ;
     RECT  2.16 10.125 23.76 10.395 ;
     RECT  2.16 10.665 23.76 10.935 ;
     RECT  2.16 11.205 23.76 11.475 ;
     RECT  2.16 11.745 23.76 12.015 ;
     RECT  2.16 12.285 23.76 12.555 ;
     RECT  2.16 12.825 23.76 13.095 ;
     RECT  2.16 13.365 23.76 13.635 ;
     RECT  2.16 13.905 23.76 14.175 ;
     RECT  2.16 14.445 23.76 14.715 ;
     RECT  2.16 14.985 23.76 15.12 ;
    LAYER RVTP ;
     RECT  2.16 2.295 23.76 2.565 ;
     RECT  2.16 2.835 23.76 3.105 ;
     RECT  2.16 3.375 23.76 3.645 ;
     RECT  2.16 3.915 23.76 4.185 ;
     RECT  2.16 4.455 23.76 4.725 ;
     RECT  2.16 4.995 23.76 5.265 ;
     RECT  2.16 5.535 23.76 5.805 ;
     RECT  2.16 6.075 23.76 6.345 ;
     RECT  2.16 6.615 23.76 6.885 ;
     RECT  2.16 7.155 23.76 7.425 ;
     RECT  2.16 7.695 23.76 7.965 ;
     RECT  2.16 8.235 23.76 8.505 ;
     RECT  2.16 8.775 23.76 9.045 ;
     RECT  2.16 9.315 23.76 9.585 ;
     RECT  2.16 9.855 23.76 10.125 ;
     RECT  2.16 10.395 23.76 10.665 ;
     RECT  2.16 10.935 23.76 11.205 ;
     RECT  2.16 11.475 23.76 11.745 ;
     RECT  2.16 12.015 23.76 12.285 ;
     RECT  2.16 12.555 23.76 12.825 ;
     RECT  2.16 13.095 23.76 13.365 ;
     RECT  2.16 13.635 23.76 13.905 ;
     RECT  2.16 14.175 23.76 14.445 ;
     RECT  2.16 14.715 23.76 14.985 ;
    LAYER M1 ;
     RECT  2.16 2.151 23.76 15.129 ;
    LAYER M2 ;
     RECT  1.039 5.616 1.111 5.634 ;
     RECT  1.075 11.286 1.111 11.304 ;
     RECT  1.111 11.286 1.255 11.502 ;
     RECT  1.039 10.44 1.291 10.458 ;
     RECT  1.291 2.916 1.327 2.934 ;
     RECT  1.291 10.368 1.327 10.458 ;
     RECT  1.255 11.286 1.327 12.078 ;
     RECT  1.327 2.916 1.363 3.366 ;
     RECT  1.327 10.368 1.363 12.078 ;
     RECT  1.147 13.176 1.399 13.194 ;
     RECT  0.823 14.256 1.399 14.274 ;
     RECT  1.363 2.916 1.435 3.438 ;
     RECT  1.255 4.266 1.435 4.284 ;
     RECT  1.399 13.176 1.507 14.274 ;
     RECT  1.435 2.916 1.579 4.284 ;
     RECT  1.363 10.098 1.579 12.078 ;
     RECT  1.579 9.936 1.615 12.078 ;
     RECT  1.507 12.906 1.795 14.274 ;
     RECT  1.579 2.376 1.831 4.284 ;
     RECT  1.111 5.076 1.831 5.634 ;
     RECT  1.795 7.236 1.867 7.254 ;
     RECT  1.615 9.36 1.867 12.078 ;
     RECT  1.795 12.906 1.867 14.436 ;
     RECT  1.867 6.552 1.975 7.254 ;
     RECT  1.687 8.316 1.975 8.334 ;
     RECT  1.831 2.376 2.16 5.634 ;
     RECT  1.975 6.552 2.16 8.334 ;
     RECT  1.867 9.36 2.16 14.436 ;
     RECT  2.16 2.151 2.263 15.129 ;
     RECT  2.335 17.118 2.371 17.136 ;
     RECT  1.867 0.144 2.543 0.162 ;
     RECT  2.263 2.106 2.551 15.129 ;
     RECT  2.551 2.07 2.587 15.129 ;
     RECT  2.371 17.118 2.651 17.208 ;
     RECT  2.551 0.216 2.687 0.234 ;
     RECT  2.587 1.728 2.831 15.129 ;
     RECT  3.415 0.216 3.487 0.234 ;
     RECT  3.127 1.152 3.587 1.17 ;
     RECT  3.487 0.144 4.063 0.234 ;
     RECT  4.027 17.19 4.063 17.208 ;
     RECT  4.063 17.118 4.163 17.208 ;
     RECT  4.063 0.144 4.235 0.324 ;
     RECT  4.235 0.144 4.559 0.234 ;
     RECT  2.831 1.998 4.927 15.129 ;
     RECT  4.927 1.926 5.143 15.129 ;
     RECT  5.143 1.926 5.467 15.21 ;
     RECT  5.467 1.224 5.611 15.21 ;
     RECT  5.611 1.152 5.639 15.282 ;
     RECT  5.639 1.152 5.711 1.17 ;
     RECT  4.559 0.144 5.863 0.162 ;
     RECT  5.863 0.144 6.143 0.234 ;
     RECT  5.639 1.926 6.179 15.282 ;
     RECT  6.179 1.926 6.431 15.174 ;
     RECT  6.511 1.152 6.871 1.17 ;
     RECT  6.871 1.152 6.971 1.242 ;
     RECT  6.143 0.144 7.015 0.162 ;
     RECT  7.015 0.144 7.051 0.234 ;
     RECT  7.051 17.118 7.087 17.136 ;
     RECT  7.087 17.118 7.187 17.208 ;
     RECT  7.051 0.144 7.223 0.324 ;
     RECT  6.971 1.152 7.259 1.17 ;
     RECT  7.223 0.144 7.367 0.234 ;
     RECT  6.431 2.106 7.555 15.174 ;
     RECT  7.555 2.106 7.835 15.282 ;
     RECT  7.835 2.106 8.339 15.174 ;
     RECT  8.239 1.152 8.843 1.17 ;
     RECT  8.339 2.106 9.391 15.129 ;
     RECT  9.535 16.074 9.671 16.092 ;
     RECT  7.367 0.144 9.823 0.162 ;
     RECT  9.823 0.144 10.327 0.234 ;
     RECT  10.399 1.152 10.463 1.17 ;
     RECT  10.327 0.144 10.499 0.324 ;
     RECT  9.391 2.106 10.651 15.174 ;
     RECT  10.651 2.106 10.823 15.318 ;
     RECT  10.823 2.106 11.147 15.246 ;
     RECT  10.939 16.074 11.255 16.092 ;
     RECT  11.147 2.106 11.435 15.174 ;
     RECT  11.587 1.152 11.687 1.17 ;
     RECT  10.499 0.144 12.199 0.162 ;
     RECT  12.199 0.144 12.371 0.324 ;
     RECT  11.435 2.106 12.667 15.129 ;
     RECT  12.667 2.106 12.739 15.174 ;
     RECT  12.739 2.106 12.839 15.318 ;
     RECT  12.811 1.152 12.947 1.17 ;
     RECT  12.371 0.144 13.343 0.162 ;
     RECT  13.315 17.118 13.351 17.136 ;
     RECT  12.839 2.151 13.631 15.318 ;
     RECT  13.351 17.118 14.171 17.208 ;
     RECT  13.631 2.151 14.359 15.129 ;
     RECT  14.359 2.034 14.395 15.129 ;
     RECT  14.395 2.034 14.539 15.174 ;
     RECT  14.539 2.034 14.675 15.21 ;
     RECT  14.071 0.144 15.215 0.162 ;
     RECT  14.107 1.152 15.215 1.17 ;
     RECT  14.675 2.034 15.475 15.174 ;
     RECT  16.051 0.144 16.339 0.162 ;
     RECT  15.475 2.034 16.591 15.246 ;
     RECT  16.339 0.144 16.915 0.234 ;
     RECT  15.943 1.152 16.915 1.17 ;
     RECT  16.591 2.034 17.167 15.354 ;
     RECT  17.167 1.998 17.347 15.354 ;
     RECT  17.347 1.998 17.555 15.399 ;
     RECT  16.915 0.144 17.995 1.17 ;
     RECT  17.995 0.144 18.239 1.242 ;
     RECT  17.555 1.998 18.247 15.174 ;
     RECT  18.247 1.881 18.355 15.174 ;
     RECT  18.355 1.881 18.815 15.399 ;
     RECT  18.239 0.144 19.471 0.864 ;
     RECT  18.815 1.881 19.471 15.174 ;
     RECT  19.471 0.144 19.715 15.174 ;
     RECT  19.715 0.846 19.787 15.174 ;
     RECT  19.787 1.881 19.795 15.174 ;
     RECT  17.923 16.236 19.795 16.254 ;
     RECT  19.795 1.881 20.191 16.254 ;
     RECT  20.191 1.881 20.435 16.704 ;
     RECT  19.787 0.846 20.515 0.864 ;
     RECT  20.435 1.881 20.515 16.254 ;
     RECT  20.515 0.846 21.127 16.254 ;
     RECT  21.127 0.306 21.163 16.254 ;
     RECT  21.163 0.144 21.551 16.254 ;
     RECT  21.091 17.118 22.055 17.208 ;
     RECT  21.551 0.144 22.235 0.9 ;
     RECT  21.551 1.881 22.667 16.254 ;
     RECT  22.667 1.998 22.739 16.254 ;
     RECT  22.739 2.034 23.171 16.254 ;
     RECT  22.235 0.846 23.575 0.9 ;
     RECT  23.171 2.034 23.639 15.669 ;
     RECT  23.575 0.846 23.747 1.17 ;
     RECT  23.639 2.034 23.76 15.129 ;
     RECT  23.747 0.846 23.819 0.9 ;
     RECT  23.76 10.638 24.071 14.544 ;
     RECT  23.76 7.398 24.143 7.416 ;
     RECT  23.76 8.361 24.251 9.108 ;
     RECT  24.071 11.178 24.359 14.544 ;
     RECT  23.76 2.034 24.431 6.534 ;
     RECT  24.359 11.178 24.431 12.852 ;
     RECT  24.431 5.706 24.575 6.534 ;
     RECT  24.575 5.706 24.611 6.264 ;
     RECT  23.819 0.882 24.647 0.9 ;
     RECT  24.251 9.09 24.647 9.108 ;
     RECT  24.431 2.034 24.683 4.824 ;
     RECT  24.683 2.034 24.719 4.599 ;
     RECT  24.431 11.178 24.719 12.816 ;
     RECT  24.719 2.034 24.755 3.744 ;
     RECT  24.755 2.844 24.827 3.744 ;
     RECT  24.719 11.646 24.827 12.816 ;
     RECT  24.827 2.844 25.079 3.564 ;
     RECT  24.719 4.581 25.115 4.599 ;
     RECT  24.827 11.646 25.115 11.97 ;
     RECT  25.079 2.916 25.187 3.564 ;
     RECT  24.359 13.986 25.187 14.544 ;
     RECT  25.187 2.916 25.223 3.294 ;
     RECT  25.115 11.646 25.223 11.889 ;
     RECT  25.223 3.276 25.259 3.294 ;
     RECT  24.611 5.706 25.295 5.724 ;
     RECT  24.827 12.798 25.295 12.816 ;
     RECT  25.187 14.526 25.331 14.544 ;
     RECT  24.755 2.034 25.367 2.052 ;
     RECT  25.223 11.871 25.799 11.889 ;
    LAYER M3 ;
     RECT  2.196 0.108 23.634 0.139 ;
     RECT  1.872 0.139 23.634 0.317 ;
     RECT  23.148 0.317 23.634 0.379 ;
     RECT  23.148 0.379 23.85 1.387 ;
     RECT  24.624 0.877 24.642 1.387 ;
     RECT  1.872 0.317 22.41 1.876 ;
     RECT  23.148 1.387 24.642 1.876 ;
     RECT  1.872 1.876 24.642 2.029 ;
     RECT  0.9 2.347 0.918 2.371 ;
     RECT  1.872 2.029 25.362 2.371 ;
     RECT  0.9 2.371 25.362 2.779 ;
     RECT  0.828 2.779 25.362 11.851 ;
     RECT  0.828 11.851 25.794 11.894 ;
     RECT  0.828 11.894 25.722 11.933 ;
     RECT  0.828 11.933 25.362 12.509 ;
     RECT  0.828 12.509 25.326 13.739 ;
     RECT  1.728 13.739 25.326 13.973 ;
     RECT  1.728 13.973 23.49 14.009 ;
     RECT  0.828 13.739 0.846 14.279 ;
     RECT  24.264 13.973 25.326 14.279 ;
     RECT  1.8 14.009 23.49 14.441 ;
     RECT  24.588 14.279 25.326 14.477 ;
     RECT  25.308 14.477 25.326 14.549 ;
     RECT  2.196 14.441 23.49 14.791 ;
     RECT  2.196 14.791 23.526 15.061 ;
     RECT  2.196 15.061 23.598 15.646 ;
     RECT  2.196 15.646 23.634 17.148 ;
     RECT  2.376 17.148 2.646 17.213 ;
     RECT  4.032 17.148 4.158 17.213 ;
     RECT  7.092 17.148 7.182 17.213 ;
     RECT  13.356 17.148 14.166 17.213 ;
     RECT  21.096 17.148 22.05 17.213 ;
    LAYER M4 ;
     RECT  0.229 3.6 0.325 3.624 ;
     RECT  0.229 12.24 0.373 12.264 ;
     RECT  0.325 3.024 0.421 3.624 ;
     RECT  0.373 5.088 0.421 5.112 ;
     RECT  0.373 12 0.421 12.264 ;
     RECT  0.277 6.912 0.469 6.936 ;
     RECT  0.421 3.024 0.517 5.112 ;
     RECT  0.469 6.288 0.517 6.936 ;
     RECT  0.421 11.52 0.757 12.264 ;
     RECT  0.277 2.016 0.805 2.04 ;
     RECT  0.805 1.92 0.817 2.04 ;
     RECT  0.517 3.024 0.817 7.464 ;
     RECT  0.325 13.296 0.853 13.32 ;
     RECT  0.817 1.92 0.857 7.464 ;
     RECT  0.853 13.296 0.997 13.368 ;
     RECT  0.997 13.296 1.141 13.416 ;
     RECT  0.857 1.92 1.573 5.544 ;
     RECT  1.573 14.928 1.621 14.952 ;
     RECT  1.573 1.872 1.861 5.544 ;
     RECT  0.857 6.624 1.861 7.464 ;
     RECT  1.861 1.872 2.005 7.464 ;
     RECT  2.005 1.872 2.053 8.04 ;
     RECT  2.053 1.872 2.101 8.136 ;
     RECT  0.757 10.608 2.149 12.264 ;
     RECT  1.141 13.296 2.149 13.656 ;
     RECT  2.149 10.608 2.197 13.656 ;
     RECT  1.621 14.64 2.197 14.952 ;
     RECT  2.101 1.872 2.245 8.28 ;
     RECT  1.861 0.192 2.291 0.216 ;
     RECT  2.197 10.608 2.293 14.952 ;
     RECT  2.245 1.728 2.408 8.28 ;
     RECT  2.293 10.608 2.408 15.288 ;
     RECT  2.408 1.728 2.704 15.288 ;
     RECT  2.704 9.696 2.725 15.288 ;
     RECT  2.725 9.696 2.837 15.336 ;
     RECT  2.293 0.288 2.869 0.312 ;
     RECT  2.704 1.728 2.869 8.52 ;
     RECT  2.869 0.288 3.443 8.52 ;
     RECT  2.837 12.192 3.493 15.336 ;
     RECT  3.443 1.152 3.635 8.52 ;
     RECT  2.837 9.696 4.129 10.968 ;
     RECT  3.635 1.392 4.405 8.52 ;
     RECT  4.549 0.288 4.885 0.312 ;
     RECT  4.129 9.696 4.885 11.16 ;
     RECT  3.493 12.192 4.885 15.432 ;
     RECT  4.885 9.696 4.979 15.432 ;
     RECT  4.405 1.392 5.108 8.568 ;
     RECT  4.979 9.696 5.108 15.288 ;
     RECT  4.885 0.288 5.123 0.408 ;
     RECT  5.108 1.392 5.404 15.288 ;
     RECT  5.123 0.288 5.555 0.312 ;
     RECT  5.404 10.608 5.717 15.288 ;
     RECT  5.717 10.608 6.433 15 ;
     RECT  6.433 9.84 6.617 15 ;
     RECT  5.404 1.392 6.757 8.28 ;
     RECT  6.617 9.84 6.757 12.504 ;
     RECT  6.709 0.192 6.851 0.216 ;
     RECT  6.949 16.56 7.093 16.584 ;
     RECT  7.093 16.56 7.193 16.632 ;
     RECT  7.429 0.288 7.477 0.312 ;
     RECT  7.477 0.288 7.763 0.408 ;
     RECT  6.757 1.392 7.808 12.504 ;
     RECT  6.617 13.536 7.808 15 ;
     RECT  7.808 1.392 7.909 15.132 ;
     RECT  7.909 1.392 8.104 15.288 ;
     RECT  7.763 0.288 8.197 0.312 ;
     RECT  8.104 14.64 8.197 15.288 ;
     RECT  7.193 16.56 8.197 16.584 ;
     RECT  8.197 14.64 8.201 16.584 ;
     RECT  8.197 0.192 8.483 0.312 ;
     RECT  8.104 1.392 8.489 10.632 ;
     RECT  8.201 14.64 8.489 16.008 ;
     RECT  8.489 1.392 8.675 10.248 ;
     RECT  8.489 14.784 9.029 16.008 ;
     RECT  8.483 0.288 9.109 0.312 ;
     RECT  8.675 1.392 9.109 8.568 ;
     RECT  9.029 14.784 9.173 14.952 ;
     RECT  9.109 0.288 9.299 8.568 ;
     RECT  8.104 11.76 9.301 12.552 ;
     RECT  8.104 13.632 9.301 13.656 ;
     RECT  8.675 9.648 9.443 10.248 ;
     RECT  9.301 11.76 9.445 13.656 ;
     RECT  9.445 11.376 9.589 13.656 ;
     RECT  9.589 11.376 9.709 14.232 ;
     RECT  9.299 1.728 9.781 8.568 ;
     RECT  9.443 9.648 9.781 9.864 ;
     RECT  9.029 15.984 9.925 16.008 ;
     RECT  9.925 15.984 10.285 16.584 ;
     RECT  9.299 0.288 10.309 0.312 ;
     RECT  9.709 10.848 10.321 14.232 ;
     RECT  10.285 15.312 10.321 16.584 ;
     RECT  10.321 10.848 10.433 16.584 ;
     RECT  9.781 1.728 10.508 9.864 ;
     RECT  10.433 10.848 10.508 16.056 ;
     RECT  10.309 0.288 10.595 0.408 ;
     RECT  10.595 0.384 10.739 0.408 ;
     RECT  10.508 1.728 10.804 16.056 ;
     RECT  10.804 14.112 10.829 16.056 ;
     RECT  10.804 1.728 10.885 9.864 ;
     RECT  10.829 14.112 11.045 14.904 ;
     RECT  10.804 10.848 11.117 12.504 ;
     RECT  10.829 15.984 11.219 16.056 ;
     RECT  11.117 10.848 11.363 11.784 ;
     RECT  10.885 1.152 11.708 9.864 ;
     RECT  11.708 0.288 11.797 9.864 ;
     RECT  11.797 13.056 11.881 13.08 ;
     RECT  11.363 11.424 12.205 11.784 ;
     RECT  11.797 0.288 12.373 10.296 ;
     RECT  11.045 14.832 12.421 14.904 ;
     RECT  12.421 14.832 12.565 14.952 ;
     RECT  12.565 14.256 12.697 14.952 ;
     RECT  12.697 14.256 13.045 15.432 ;
     RECT  11.509 16.56 13.093 16.584 ;
     RECT  13.045 14.208 13.148 15.432 ;
     RECT  13.093 16.56 13.148 16.632 ;
     RECT  12.373 0.288 13.208 10.344 ;
     RECT  12.205 11.76 13.208 11.784 ;
     RECT  12.229 12.864 13.208 12.888 ;
     RECT  13.148 14.208 13.208 16.632 ;
     RECT  13.208 0.288 13.504 16.632 ;
     RECT  13.504 0.288 13.66 11.784 ;
     RECT  13.66 0.288 14.101 1.32 ;
     RECT  13.504 14.208 14.105 16.632 ;
     RECT  14.101 0.144 14.435 1.32 ;
     RECT  13.66 2.304 14.569 11.784 ;
     RECT  13.504 12.864 14.569 13.032 ;
     RECT  14.435 0.144 14.627 1.224 ;
     RECT  14.569 2.304 14.917 13.032 ;
     RECT  14.917 2.304 15.505 13.128 ;
     RECT  14.105 14.352 15.505 16.632 ;
     RECT  15.505 2.304 15.613 16.632 ;
     RECT  15.613 2.256 15.908 16.632 ;
     RECT  14.627 0.144 16.049 1.176 ;
     RECT  16.049 0.24 16.093 1.176 ;
     RECT  16.093 0.288 16.309 1.176 ;
     RECT  15.908 2.148 16.309 16.632 ;
     RECT  16.309 0.288 16.369 16.632 ;
     RECT  16.369 0.288 16.547 16.728 ;
     RECT  16.547 2.256 16.589 16.728 ;
     RECT  16.547 0.288 17.125 1.176 ;
     RECT  17.125 0.192 17.411 1.176 ;
     RECT  17.411 0.288 17.459 1.176 ;
     RECT  16.589 15.984 17.669 16.728 ;
     RECT  16.589 2.256 17.773 15 ;
     RECT  17.669 16.56 18.209 16.728 ;
     RECT  17.459 0.288 18.421 0.312 ;
     RECT  18.421 0.288 18.469 0.36 ;
     RECT  17.773 2.256 18.608 15.48 ;
     RECT  18.608 2.148 18.853 15.48 ;
     RECT  18.209 16.656 19.043 16.728 ;
     RECT  18.469 0.288 19.093 0.456 ;
     RECT  18.853 1.728 19.093 15.48 ;
     RECT  19.093 0.288 19.187 15.48 ;
     RECT  19.187 0.288 20.069 14.952 ;
     RECT  19.333 15.984 20.08 16.584 ;
     RECT  20.08 15.984 20.225 16.632 ;
     RECT  20.069 0.192 20.869 14.952 ;
     RECT  20.225 15.984 20.869 16.584 ;
     RECT  20.869 0.192 21.395 16.584 ;
     RECT  21.395 0.192 22.421 15.24 ;
     RECT  22.421 8.016 22.633 15.24 ;
     RECT  21.395 16.56 22.633 16.584 ;
     RECT  22.421 0.192 23.105 6.936 ;
     RECT  22.633 8.016 23.123 16.584 ;
     RECT  23.105 0.192 23.609 6.696 ;
     RECT  23.123 15.984 23.644 16.584 ;
     RECT  23.609 0.24 23.717 6.696 ;
     RECT  23.644 16.56 23.747 16.584 ;
     RECT  23.123 8.016 23.789 14.952 ;
     RECT  23.789 8.016 23.933 9.816 ;
     RECT  23.933 8.016 23.969 9.672 ;
     RECT  23.717 0.24 24.275 6.36 ;
     RECT  24.275 2.496 24.323 6.36 ;
     RECT  24.275 0.24 24.329 1.416 ;
     RECT  24.323 3.216 24.371 6.36 ;
     RECT  23.969 9.072 24.401 9.672 ;
     RECT  23.789 10.944 24.545 14.952 ;
     RECT  23.969 8.016 24.563 8.04 ;
     RECT  24.371 3.312 24.611 6.36 ;
     RECT  24.401 9.36 24.611 9.672 ;
     RECT  24.611 3.312 24.659 6.072 ;
     RECT  24.545 11.472 24.659 14.952 ;
     RECT  24.329 0.24 24.707 1.176 ;
     RECT  24.659 11.472 24.707 13.464 ;
     RECT  24.707 11.616 24.755 13.464 ;
     RECT  24.707 0.24 24.803 0.264 ;
     RECT  24.659 14.928 24.851 14.952 ;
     RECT  24.659 3.552 24.899 6.072 ;
     RECT  24.755 11.616 24.899 13.416 ;
     RECT  24.899 5.424 25.157 6.072 ;
     RECT  24.611 9.36 25.157 9.384 ;
     RECT  24.899 11.616 25.265 12.504 ;
     RECT  24.899 3.552 25.337 3.576 ;
     RECT  25.265 11.856 25.373 12.504 ;
     RECT  25.157 5.424 25.74 5.448 ;
     RECT  25.373 11.856 25.74 11.928 ;
     RECT  25.74 11.856 25.805 11.88 ;
    LAYER M5 ;
     RECT  14.112 0.133 14.136 0.144 ;
     RECT  2.256 0.144 23.736 0.181 ;
     RECT  1.872 0.181 23.736 1.141 ;
     RECT  24.768 0.229 24.792 1.141 ;
     RECT  1.872 1.141 24.792 1.861 ;
     RECT  1.584 1.861 24.792 1.909 ;
     RECT  0.816 1.909 24.792 2.005 ;
     RECT  0.288 2.005 24.792 3.589 ;
     RECT  0.24 3.589 24.792 4.213 ;
     RECT  0.24 4.213 24.84 4.501 ;
     RECT  0.24 4.501 24.888 8.003 ;
     RECT  0.24 8.003 6.792 8.147 ;
     RECT  6.768 8.147 6.792 9.155 ;
     RECT  7.8 8.003 24.888 10.259 ;
     RECT  9.744 10.259 24.888 10.307 ;
     RECT  13.2 10.307 24.888 10.835 ;
     RECT  9.744 10.307 12.168 10.883 ;
     RECT  13.2 10.835 13.656 10.883 ;
     RECT  0.24 8.147 5.412 11.365 ;
     RECT  7.8 10.259 8.52 11.365 ;
     RECT  9.744 10.883 10.812 11.365 ;
     RECT  12.096 10.883 12.168 11.459 ;
     RECT  12.096 11.459 12.12 11.555 ;
     RECT  0.24 11.365 6.216 11.701 ;
     RECT  0.24 11.701 6.504 12.275 ;
     RECT  7.8 11.365 10.812 12.563 ;
     RECT  15.9 10.835 24.888 12.563 ;
     RECT  20.88 12.563 24.888 12.659 ;
     RECT  15.9 12.563 19.128 12.899 ;
     RECT  15.9 12.899 18.912 13.093 ;
     RECT  0.336 12.275 6.504 13.331 ;
     RECT  0.864 13.331 6.504 13.379 ;
     RECT  1.008 13.379 6.504 13.427 ;
     RECT  21.3 12.659 24.888 13.427 ;
     RECT  1.584 13.427 6.504 13.763 ;
     RECT  13.2 10.883 13.512 14.197 ;
     RECT  7.8 12.563 8.112 14.245 ;
     RECT  11.808 13.045 11.832 14.245 ;
     RECT  13.056 14.197 13.512 14.245 ;
     RECT  14.928 13.093 18.912 14.245 ;
     RECT  21.3 13.427 24.84 14.483 ;
     RECT  7.584 14.245 8.112 14.773 ;
     RECT  9.312 12.563 10.812 14.773 ;
     RECT  1.584 13.763 3.864 14.821 ;
     RECT  4.896 13.763 6.504 14.821 ;
     RECT  7.584 14.773 10.812 14.821 ;
     RECT  11.808 14.245 13.512 14.821 ;
     RECT  14.928 14.245 19.512 14.821 ;
     RECT  21.3 14.483 23.4 14.821 ;
     RECT  1.584 14.821 23.4 14.963 ;
     RECT  24.816 14.483 24.84 14.963 ;
     RECT  2.256 14.963 23.4 15.973 ;
     RECT  2.256 15.973 23.592 16.549 ;
     RECT  2.256 16.549 23.736 17.104 ;
  END
END dsfd_dvrly_276_SN
END LIBRARY
